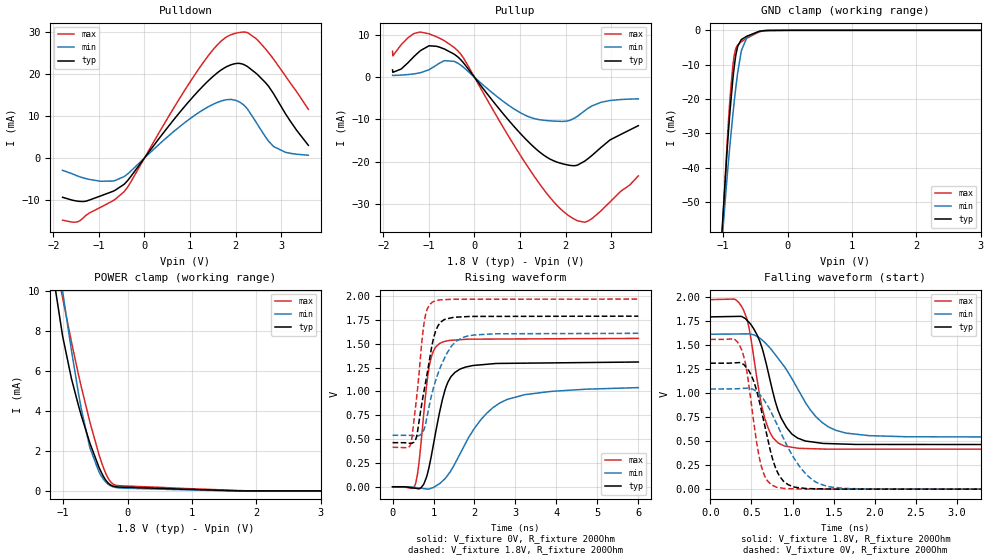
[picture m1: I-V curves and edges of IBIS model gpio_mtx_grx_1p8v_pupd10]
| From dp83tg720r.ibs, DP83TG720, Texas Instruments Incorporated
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|   gpio_mtx_grx_1p8v_pupd10
[Model]   gpio_mtx_grx_1p8v_pupd10
Model_type   I/O
Polarity   Non-Inverting
Enable   Active-Low
Vinl = 0.54
Vinh = 1.26
Vmeas = 0.9
Vref = 0
Cref = 2pF
Rref = 100000
|   typ   min   max
C_comp   1.46pF   1.44pF   1.48pF
[Voltage Range]   1.8   1.62   1.98
[Temperature Range]   27   150   -40
[Pullup Reference]   1.8   1.62   1.98
[Pulldown Reference]   0   0   0
[Power Clamp Reference]   1.8   1.62   1.98
[GND Clamp Reference]   0   0   0
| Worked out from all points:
|   slope of the pulldown table from 0 to 0.27 V, typ, clamps not added: 68.8 ohm
|   slope of the pullup table from 0 to 0.27 V, typ, clamps not added: 71.1 ohm
|   GND clamp passes 1 mA (typ) near -0.54 V on its own axis
|   POWER clamp passes 1 mA (typ) near -0.42 V on its own axis
|   falling waveform, V_fixture 1.8V, R_fixture 200Ohm: 20-80 % time 262ps typ, 492ps min, 192ps max; typ from 1.79 V to 0.463 V
|   rising waveform, V_fixture 0V, R_fixture 200Ohm: 20-80 % time 387ps typ, 980ps min, 228ps max; typ from 0 V to 1.31 V
|   rising waveform, V_fixture 1.8V, R_fixture 200Ohm: 20-80 % time 321ps typ, 472ps min, 220ps max; typ from 0.463 V to 1.79 V
|   falling waveform, V_fixture 0V, R_fixture 200Ohm: 20-80 % time 222ps typ, 390ps min, 160ps max; typ from 1.31 V to 0 V
[Pulldown]
|   Voltage   I(typ)   I(min)   I(max)
-1.8V     -9.373mA   -2.955mA   -14.83mA
-1.503V   -10.24mA   -4.167mA   -15.29mA
-1.287V   -10.3mA    -4.916mA   -13.7mA
-698.4mV  -7.972mA   -5.494mA   -10.23mA
-444.6mV  -6.254mA   -4.425mA   -8.011mA
1.143V    15.5mA     10.46mA    20.44mA
1.597V    20.26mA    13.22mA    26.92mA
1.894V    22.18mA    13.95mA    29.34mA
2.174V    22.29mA    12.67mA    30mA
2.45V     20.2mA     8.58mA     28.46mA
2.839V    15.27mA    2.714mA    23.52mA
3.6V      3.022mA    656uA      11.6mA
[GND Clamp]
|   Voltage   I(typ)   I(min)   I(max)
-1.8V     -346.2mA   -302.9mA   -380.4mA
-1.012V   -56.7mA    -60.05mA   -58.37mA
-941.4mV  -35.77mA   -43.43mA   -33.93mA
-898.2mV  -24.65mA   -34.19mA   -21.03mA
-849.6mV  -14.29mA   -24.7mA    -10.27mA
-833.4mV  -11.45mA   -21.77mA   -7.914mA
-801mV    -6.989mA   -16.32mA   -5.181mA
-774mV    -4.661mA   -12.31mA   -4.247mA
-720mV    -2.755mA   -6.237mA   -3.369mA
-628.2mV  -1.684mA   -1.968mA   -2.249mA
-293.4mV  -41.03uA   -39.78uA   -54.54uA
3.6V      0A         0A         0A
[Pullup]
|   Voltage   I(typ)   I(min)   I(max)
-1.8V     1.744mA    480.7uA    6.165mA
-1.795V   1.177mA    422.4uA    5.078mA
-1.611V   1.951mA    521.8uA    7.703mA
-1.206V   6.14mA     1.032mA    10.69mA
-828mV    7.327mA    2.927mA    9.562mA
-444.6mV  5.46mA     3.759mA    7.052mA
-223.2mV  3.171mA    2.189mA    4.237mA
1.138V    -14.78mA   -9.105mA   -20.64mA
1.672V    -19.44mA   -10.32mA   -28.64mA
2.25V     -20.85mA   -9.32mA    -33.92mA
2.59V     -18.43mA   -6.745mA   -33.39mA
3.6V      -11.46mA   -5.119mA   -23.35mA
[POWER Clamp]
|   Voltage   I(typ)   I(min)   I(max)
-1.8V     53.03mA    32.09mA    32.8mA
-1.13V    10.31mA    12.75mA    11.79mA
-1.006V   7.723mA    9.944mA    9.63mA
-871.2mV  5.628mA    7.042mA    7.462mA
-720mV    3.797mA    4.133mA    5.24mA
-585mV    2.398mA    2.165mA    3.454mA
-444.6mV  1.193mA    960.8uA    1.835mA
-347.4mV  586.3uA    482.8uA    949uA
-271.8mV  317uA      272.9uA    491.2uA
-142.2mV  198.3uA    155.7uA    266.6uA
1.067V    69.49uA    43.45uA    98.19uA
3.6V      0A         0A         0A
[Ramp]
R_load = 200
|   typ   min   max
dV/dt_r   0.785476/3.86403e-10   0.624337/9.79154e-10   0.934047/2.27086e-10
dV/dt_f   0.796658/2.61052e-10   0.642069/4.88383e-10   0.93308/1.91646e-10
[Falling Waveform]
V_fixture = 1.8V
V_fixture_min = 1.62V
V_fixture_max = 1.98V
R_fixture = 200Ohm
C_fixture = 0F
|   Time   V(typ)   V(min)   V(max)
0s        1.791V     1.61V      1.97V
290.4ps   1.795V     1.613V     1.976V
397.8ps   1.787V     1.613V     1.872V
471.5ps   1.733V     1.614V     1.673V
663.8ps   1.358V     1.524V     733.2mV
788.5ps   915.4mV    1.399V     510.8mV
901.7ps   678.6mV    1.273V     448.6mV
1.28ns    486.2mV    757.7mV    419.7mV
1.65ns    468.1mV    582.8mV    416.3mV
6ns       462.8mV    540.3mV    414.9mV
[Rising Waveform]
V_fixture = 0V
V_fixture_min = 0V
V_fixture_max = 0V
R_fixture = 200Ohm
C_fixture = 0F
|   Time   V(typ)   V(min)   V(max)
0s        265.6uV    155.4uV    420.8uV
556.8ps   -15.77mV   -7.668mV   27.88mV
645.8ps   -21.29mV   -12.58mV   254.4mV
888.2ps   200.7mV    -23.76mV   1.247V
1.148ns   783.5mV    33.2mV     1.504V
1.307ns   1.051V     99.22mV    1.528V
1.518ns   1.199V     239.9mV    1.54V
2.133ns   1.279V     691.7mV    1.55V
2.791ns   1.295V     915.3mV    1.551V
6ns       1.309V     1.041V     1.557V
[Rising Waveform]
V_fixture = 1.8V
V_fixture_min = 1.62V
V_fixture_max = 1.98V
R_fixture = 200Ohm
C_fixture = 0F
|   Time   V(typ)   V(min)   V(max)
0s        462.8mV    540.3mV    414.9mV
447.9ps   456.6mV    538.8mV    456.6mV
584.5ps   523.5mV    533.8mV    926.7mV
767.5ps   1.004V     600mV      1.715V
850.8ps   1.204V     755.5mV    1.869V
975.4ps   1.511V     1V         1.938V
1.11ns    1.691V     1.189V     1.958V
1.427ns   1.772V     1.47V      1.967V
1.837ns   1.786V     1.582V     1.968V
6ns       1.791V     1.61V      1.97V
[Falling Waveform]
|Gnd
V_fixture = 0V
V_fixture_min = 0V
V_fixture_max = 0V
R_fixture = 200Ohm
C_fixture = 0F
|   Time   V(typ)   V(min)   V(max)
0s        1.31V      1.041V     1.557V
280.9ps   1.312V     1.042V     1.563V
373.6ps   1.312V     1.046V     1.464V
426ps     1.277V     1.049V     1.311V
495.4ps   1.188V     1.044V     910mV
617.6ps   831.6mV    967.2mV    247.4mV
803.4ps   199.4mV    686.5mV    20.74mV
1.105ns   12.93mV    214.1mV    1.587mV
1.475ns   1.345mV    21.17mV    1.305mV
6ns       265.7uV    155.4uV    421.2uV
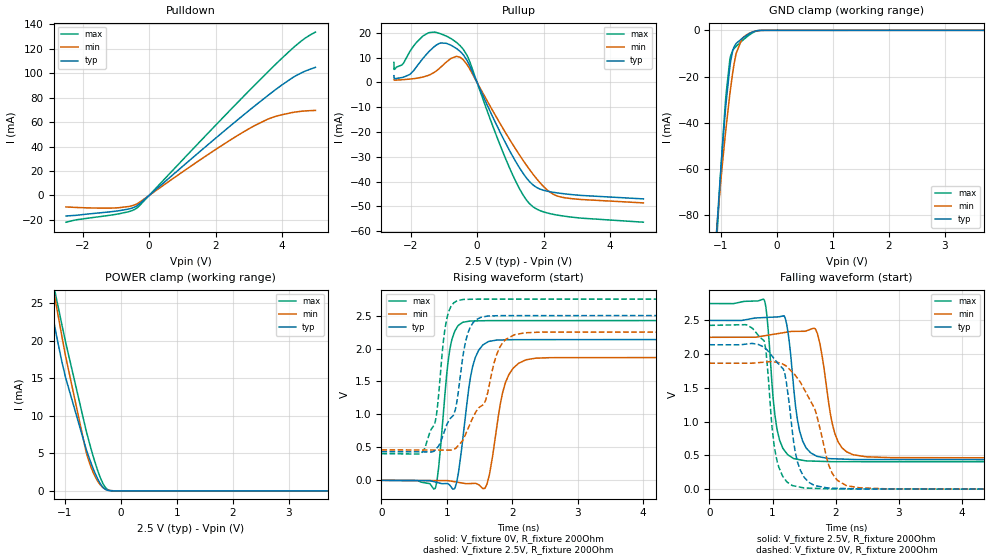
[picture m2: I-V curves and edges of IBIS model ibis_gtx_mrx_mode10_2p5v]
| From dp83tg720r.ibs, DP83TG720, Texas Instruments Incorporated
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| ibis_gtx_mrx_mode10_2p5v
[Model]   ibis_gtx_mrx_mode10_2p5v
Model_type   I/O
Polarity   Non-Inverting
Enable   Active-Low
Vinl = 0.75
Vinh = 1.75
Vmeas = 1.25
Vref = 1.25
Cref = 2pF
Rref = 100000
|   typ   min   max
C_comp   2.91pF   2.87pF   2.94pF
[Voltage Range]   2.5   2.25   2.75
[Temperature Range]   27   150   -40
[Pullup Reference]   2.5   2.25   2.75
[Pulldown Reference]   0   0   0
[Power Clamp Reference]   2.5   2.25   2.75
[GND Clamp Reference]   0   0   0
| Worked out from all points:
|   slope of the pulldown table from 0 to 0.375 V, typ, clamps not added: 42.1 ohm
|   slope of the pullup table from 0 to 0.375 V, typ, clamps not added: 33.6 ohm
|   GND clamp passes 1 mA (typ) near -0.45 V on its own axis
|   POWER clamp passes 1 mA (typ) near -0.37 V on its own axis
|   falling waveform, V_fixture 2.5V, R_fixture 200Ohm: 20-80 % time 157ps typ, 190ps min, 136ps max; typ from 2.5 V to 0.435 V
|   rising waveform, V_fixture 0V, R_fixture 200Ohm: 20-80 % time 171ps typ, 199ps min, 137ps max; typ from 0 V to 2.14 V
|   rising waveform, V_fixture 2.5V, R_fixture 200Ohm: 20-80 % time 283ps typ, 417ps min, 150ps max; typ from 0.435 V to 2.5 V
|   falling waveform, V_fixture 0V, R_fixture 200Ohm: 20-80 % time 194ps typ, 391ps min, 149ps max; typ from 2.14 V to 0 V
[Pulldown]
|   Voltage   I(typ)   I(min)   I(max)
-2.5V     -16.83mA   -9.441mA   -21.92mA
-2.185V   -16.25mA   -9.858mA   -19.94mA
-1.083V   -13.14mA   -10.32mA   -15.85mA
-617.5mV  -11.15mA   -9.099mA   -13.35mA
-362.5mV  -8.408mA   -6.814mA   -10.19mA
1.798V    42.21mA    33.95mA    51.74mA
2.533V    59mA       46.91mA    72.51mA
3.147V    72.69mA    56.82mA    89.62mA
3.74V     85.35mA    64.15mA    105.7mA
4.28V     95.82mA    67.74mA    119.6mA
4.692V    101.8mA    69.17mA    128.8mA
5V        104.8mA    69.59mA    133.7mA
[GND Clamp]
|   Voltage   I(typ)   I(min)   I(max)
-2.5V     -672.4mA   -578.6mA   -749.1mA
-1.097V   -97.01mA   -94.22mA   -103.2mA
-1.03V    -72.28mA   -74.57mA   -74.7mA
-962.5mV  -49.34mA   -56.59mA   -48.07mA
-917.5mV  -35.71mA   -45.65mA   -32.42mA
-835mV    -16.02mA   -27.78mA   -12.86mA
-782.5mV  -8.753mA   -18.2mA    -8.647mA
-722.5mV  -5.688mA   -10.01mA   -6.949mA
-617.5mV  -3.554mA   -3.702mA   -4.596mA
-467.5mV  -1.199mA   -1.052mA   -1.675mA
-272.5mV  -16.77uA   -38.63uA   -18.24uA
5V        0A         0A         0A
[Pullup]
|   Voltage   I(typ)   I(min)   I(max)
-2.5V     2.729mA    1.091mA    8.084mA
-2.493V   1.51mA     925.7uA    5.246mA
-2.268V   1.963mA    1.093mA    7.013mA
-2.02V    3.254mA    1.361mA    12.53mA
-1.472V   12.09mA    2.813mA    19.97mA
-1.135V   15.76mA    5.648mA    19.84mA
-790mV    15.09mA    9.669mA    17.78mA
-287.5mV  8.575mA    6.935mA    10.56mA
852.5mV   -24.33mA   -20.2mA    -30.6mA
1.587V    -40.18mA   -35.34mA   -49.09mA
2.428V    -44.63mA   -45.92mA   -53.59mA
5V        -47.02mA   -48.64mA   -56.43mA
[POWER Clamp]
|   Voltage   I(typ)   I(min)   I(max)
-2.5V     144.5mA    109.4mA    191.7mA
-1.42V    32.38mA    36.09mA    36.29mA
-1.248V   24.72mA    28.69mA    29.23mA
-1.15V    20.76mA    24.63mA    25.64mA
-985mV    15.08mA    17.93mA    19.8mA
-617.5mV  5.56mA     5.156mA    8.015mA
-550mV    4.113mA    3.562mA    6.126mA
-460mV    2.396mA    1.954mA    3.822mA
-355mV    860uA      725.3uA    1.597mA
-257.5mV  148.6uA    170.2uA    327.9uA
-92.5mV   988.6nA    4.315uA    1.238uA
5V        0A         0A         0A
[Ramp]
R_load = 200
|   typ   min   max
dV/dt_r   1.28225/1.70637e-10   1.11858/1.99144e-10   1.45475/1.35625e-10
dV/dt_f   1.23902/1.55855e-10   1.07266/1.89547e-10   1.40735/1.36094e-10
[Falling Waveform]
V_fixture = 2.5V
V_fixture_min = 2.25V
V_fixture_max = 2.75V
R_fixture = 200Ohm
C_fixture = 0F
|   Time   V(typ)   V(min)   V(max)
0s        2.5V       2.25V      2.75V
868ps     2.543V     2.272V     2.805V
1.072ns   2.552V     2.303V     883.2mV
1.206ns   2.516V     2.324V     551.9mV
1.331ns   1.534V     2.338V     454.3mV
1.476ns   714.1mV    2.339V     428mV
1.681ns   497.3mV    2.367V     414.6mV
1.98ns    449.8mV    842.3mV    407.3mV
2.267ns   440.4mV    512.7mV    407.1mV
6ns       435mV      462.3mV    404.5mV
[Rising Waveform]
V_fixture = 0V
V_fixture_min = 0V
V_fixture_max = 0V
R_fixture = 200Ohm
C_fixture = 0F
|   Time   V(typ)   V(min)   V(max)
0s        1.569uV    20.51uV    733.6nV
820.6ps   -24.9mV    -2.975mV   -123.4mV
1.044ns   -71mV      -8.529mV   1.974V
1.149ns   -35.57mV   -26.32mV   2.31V
1.239ns   587.4mV    -41.45mV   2.395V
1.489ns   1.977V     -67.63mV   2.42V
1.614ns   2.093V     -55.32mV   2.422V
1.898ns   2.131V     1.487V     2.423V
2.199ns   2.134V     1.824V     2.423V
6ns       2.137V     1.864V     2.425V
[Rising Waveform]
V_fixture = 2.5V
V_fixture_min = 2.25V
V_fixture_max = 2.75V
R_fixture = 200Ohm
C_fixture = 0F
|   Time   V(typ)   V(min)   V(max)
0s        435mV      462.3mV    404.5mV
661.8ps   431.7mV    460.1mV    483.6mV
835.1ps   475.7mV    459.5mV    954.5mV
998.4ps   842.9mV    458.9mV    2.45V
1.16ns    1.237V     512.6mV    2.727V
1.287ns   2.108V     700.3mV    2.745V
1.403ns   2.393V     959.8mV    2.748V
1.808ns   2.499V     2.015V     2.749V
2.035ns   2.499V     2.209V     2.749V
6ns       2.5V       2.25V      2.75V
[Falling Waveform]
|Gnd
V_fixture = 0V
V_fixture_min = 0V
V_fixture_max = 0V
R_fixture = 200Ohm
C_fixture = 0F
|   Time   V(typ)   V(min)   V(max)
0s        2.14V      1.866V     2.427V
861.8ps   2.1V       1.881V     2.203V
1.053ns   1.9V       1.881V     495.4mV
1.192ns   1.72V      1.837V     151.6mV
1.311ns   868.5mV    1.734V     54.28mV
1.398ns   393.2mV    1.639V     36.98mV
1.571ns   102.8mV    1.358V     15.15mV
1.935ns   16.12mV    253.8mV    3.348mV
2.163ns   8.783mV    55.26mV    2.931mV
6ns       1.684uV    20.54uV    725.1nV
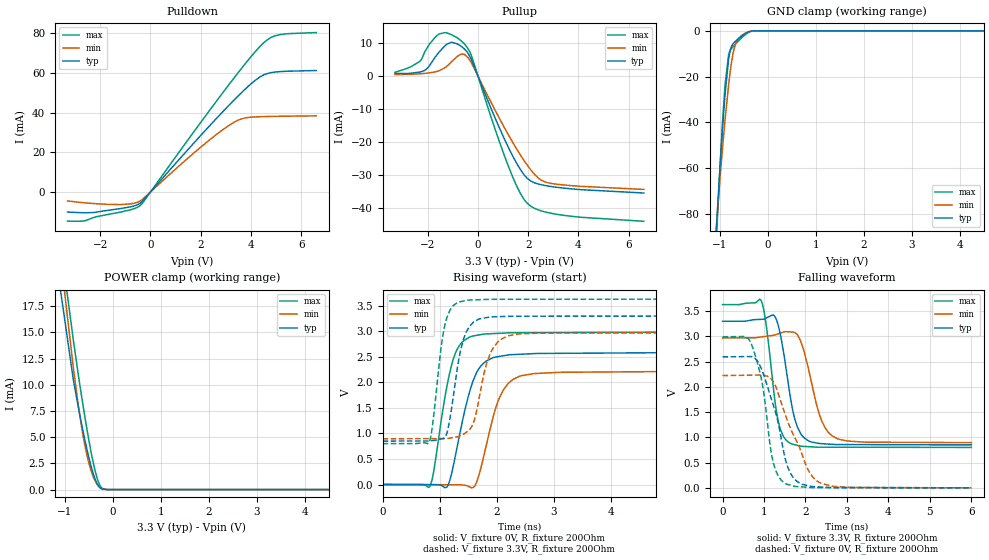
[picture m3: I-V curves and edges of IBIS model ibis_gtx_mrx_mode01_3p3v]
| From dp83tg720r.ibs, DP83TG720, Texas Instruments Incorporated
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| ibis_gtx_mrx_mode10_3p3v
[Model]   ibis_gtx_mrx_mode01_3p3v
Model_type   I/O
Polarity   Non-Inverting
Enable   Active-Low
Vinl = 0.99
Vinh = 2.31
Vmeas = 1.65
Vref = 1.65
Cref = 2pF
Rref = 100000
|   typ   min   max
C_comp   2.88pF   2.85pF   2.91pF
[Voltage Range]   3.3   2.97   3.63
[Temperature Range]   27   150   -40
[Pullup Reference]   3.3   2.97   3.63
[Pulldown Reference]   0   0   0
[Power Clamp Reference]   3.3   2.97   3.63
[GND Clamp Reference]   0   0   0
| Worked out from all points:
|   slope of the pulldown table from 0 to 0.495 V, typ, clamps not added: 69.2 ohm
|   slope of the pullup table from 0 to 0.495 V, typ, clamps not added: 53.2 ohm
|   GND clamp passes 1 mA (typ) near -0.45 V on its own axis
|   POWER clamp passes 1 mA (typ) near -0.37 V on its own axis
|   falling waveform, V_fixture 3.3V, R_fixture 200Ohm: 20-80 % time 306ps typ, 389ps min, 253ps max; typ from 3.3 V to 0.85 V
|   rising waveform, V_fixture 0V, R_fixture 200Ohm: 20-80 % time 333ps typ, 333ps min, 278ps max; typ from 0 V to 2.59 V
|   rising waveform, V_fixture 3.3V, R_fixture 200Ohm: 20-80 % time 221ps typ, 262ps min, 183ps max; typ from 0.85 V to 3.3 V
|   falling waveform, V_fixture 0V, R_fixture 200Ohm: 20-80 % time 474ps typ, 637ps min, 330ps max; typ from 2.59 V to 0 V
[Pulldown]
|   Voltage   I(typ)   I(min)   I(max)
-3.3V     -10.08mA   -4.49mA    -14.66mA
-2.666V   -10.42mA   -5.368mA   -14.59mA
-2.28V    -10.33mA   -5.764mA   -12.91mA
-1.211V   -8.365mA   -6.324mA   -10.16mA
-429mV    -5.796mA   -4.673mA   -6.987mA
1.818V    25.94mA    20.63mA    31.91mA
2.986V    41.87mA    32.34mA    51.81mA
3.62V     49.98mA    36.81mA    62.2mA
4.392V    58.22mA    37.95mA    73.74mA
4.769V    60.04mA    38.06mA    77.63mA
4.966V    60.42mA    38.11mA    78.69mA
6.6V      61.18mA    38.36mA    80.29mA
[GND Clamp]
|   Voltage   I(typ)   I(min)   I(max)
-3.3V     -1.011A    -865.8mA   -1.126A
-1.082V   -91.37mA   -89.71mA   -96.69mA
-1.053V   -80.45mA   -81.02mA   -84.12mA
-963.6mV  -49.69mA   -56.87mA   -48.48mA
-894.3mV  -29.4mA    -40.34mA   -25.48mA
-815.1mV  -12.66mA   -23.94mA   -10.6mA
-765.6mV  -7.479mA   -15.54mA   -8.067mA
-726mV    -5.787mA   -10.39mA   -7.032mA
-676.5mV  -4.645mA   -6.247mA   -5.893mA
-567.6mV  -2.701mA   -2.49mA    -3.55mA
-419.1mV  -641.7uA   -598uA     -944.7uA
6.6V      0A         0A         0A
[Pullup]
|   Voltage   I(typ)   I(min)   I(max)
-3.3V     793.6uA    461.8uA    1.11mA
-2.33V    1.194mA    667.6uA    4.324mA
-2.132V   1.671mA    787.5uA    7.026mA
-1.538V   7.318mA    1.632mA    12.73mA
-1.053V   10.25mA    4.299mA    12.52mA
-815.1mV  9.709mA    6.001mA    11.52mA
-537.9mV  8.156mA    6.499mA    9.707mA
-280.5mV  5.302mA    4.258mA    6.565mA
1.125V    -20.21mA   -16.6mA    -25.56mA
1.957V    -30.89mA   -26.91mA   -38.43mA
2.788V    -33.27mA   -32.3mA    -41.31mA
6.6V      -35.38mA   -34.29mA   -43.94mA
[POWER Clamp]
|   Voltage   I(typ)   I(min)   I(max)
-3.3V     317.9mA    237mA      400.5mA
-1.181V   21.99mA    25.93mA    26.78mA
-815.1mV  10.35mA    11.45mA    14.1mA
-656.7mV  6.45mA     6.234mA    9.162mA
-587.4mV  4.9mA      4.403mA    7.158mA
-528mV    3.668mA    3.117mA    5.537mA
-458.7mV  2.373mA    1.935mA    3.791mA
-369.6mV  1.032mA    856.8uA    1.866mA
-310.2mV  435.4uA    402.4uA    888uA
-231mV    77.39uA    103.3uA    169.6uA
-62.7mV   288.6nA    1.815uA    282.8nA
6.6V      0A         0A         0A
[Ramp]
R_load = 200
|   typ   min   max
dV/dt_r   1.55273/3.31035e-10   1.3319/3.30138e-10   1.79224/2.77973e-10
dV/dt_f   1.46973/3.03358e-10   1.24475/3.85363e-10   1.69754/2.53071e-10
[Falling Waveform]
V_fixture = 3.3V
V_fixture_min = 2.97V
V_fixture_max = 3.63V
R_fixture = 200Ohm
C_fixture = 0F
|   Time   V(typ)   V(min)   V(max)
0s        3.3V       2.97V      3.63V
934.3ps   3.338V     2.989V     3.709V
1.053ns   3.363V     3.003V     3.228V
1.295ns   3.344V     3.038V     1.539V
1.458ns   2.753V     3.083V     1.036V
1.626ns   1.85V      3.09V      885.9mV
1.92ns    1.033V     2.821V     823.6mV
2.324ns   880.7mV    1.485V     805.4mV
2.64ns    862.5mV    1.034V     805mV
6ns       850.3mV    895.2mV    800.7mV
[Rising Waveform]
V_fixture = 0V
V_fixture_min = 0V
V_fixture_max = 0V
R_fixture = 200Ohm
C_fixture = 0F
|   Time   V(typ)   V(min)   V(max)
0s        2.566uV    32.31uV    1.213uV
825.4ps   -2.166mV   -3.183mV   -39.96mV
893.8ps   -2.345mV   -3.449mV   249.4mV
1.151ns   1.238mV    -4.451mV   2.064V
1.303ns   723mV      -5.041mV   2.642V
1.518ns   1.797V     -44.61mV   2.884V
1.653ns   2.208V     68.62mV    2.922V
2.041ns   2.509V     1.69V      2.961V
2.394ns   2.55V      2.119V     2.972V
6ns       2.588V     2.22V      2.987V
[Rising Waveform]
V_fixture = 3.3V
V_fixture_min = 2.97V
V_fixture_max = 3.63V
R_fixture = 200Ohm
C_fixture = 0F
|   Time   V(typ)   V(min)   V(max)
0s        850.3mV    895.2mV    800.7mV
814.3ps   853.4mV    898.9mV    821.4mV
1.077ns   909.4mV    900.1mV    3.056V
1.171ns   1.242V     907.8mV    3.393V
1.324ns   2.386V     938.8mV    3.57V
1.42ns    2.857V     987.5mV    3.594V
1.596ns   3.186V     1.232V     3.615V
1.877ns   3.279V     2.546V     3.626V
2.204ns   3.293V     2.913V     3.627V
6ns       3.3V       2.97V      3.63V
[Falling Waveform]
|Gnd
V_fixture = 0V
V_fixture_min = 0V
V_fixture_max = 0V
R_fixture = 200Ohm
C_fixture = 0F
|   Time   V(typ)   V(min)   V(max)
0s        2.593V     2.224V     2.991V
532.5ps   2.6V       2.23V      2.998V
694.4ps   2.6V       2.232V     2.852V
959.6ps   2.311V     2.235V     2.066V
1.219ns   1.654V     2.108V     518.2mV
1.496ns   635.4mV    1.491V     95.94mV
1.774ns   141.8mV    945mV      26.55mV
2.119ns   32.99mV    277mV      8.053mV
2.389ns   14.95mV    85.06mV    5.407mV
6ns       2.644uV    32.39uV    1.331uV
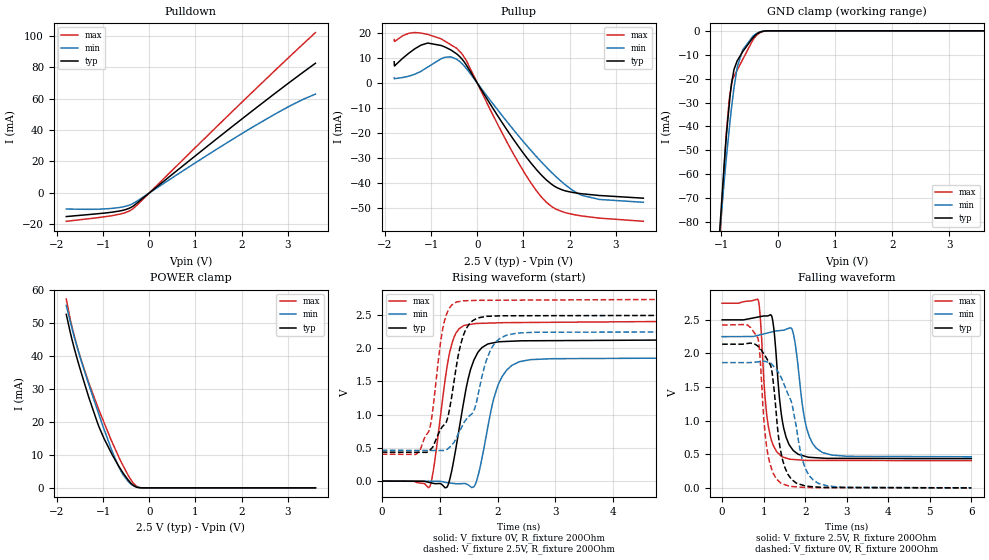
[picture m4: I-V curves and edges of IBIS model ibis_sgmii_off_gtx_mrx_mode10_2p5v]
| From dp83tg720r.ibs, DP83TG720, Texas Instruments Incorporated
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| ibis_sgmii_off_gtx_mrx_mode10_2p5v
[Model]   ibis_sgmii_off_gtx_mrx_mode10_2p5v
Model_type   I/O
Polarity   Non-Inverting
Enable   Active-Low
Vinl = 0.75
Vinh = 1.75
Vmeas = 1.25
Vref = 1.25
Cref = 2pF
Rref = 100000
|   typ   min   max
C_comp   3.97pF   3.9pF   4.02pF
[Voltage Range]   2.5   2.25   2.75
[Temperature Range]   27   150   -40
[Pullup Reference]   2.5   2.25   2.75
[Pulldown Reference]   0   0   0
[Power Clamp Reference]   2.5   2.25   2.75
[GND Clamp Reference]   0   0   0
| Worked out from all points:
|   slope of the pulldown table from 0 to 0.375 V, typ, clamps not added: 42.1 ohm
|   slope of the pullup table from 0 to 0.375 V, typ, clamps not added: 33.6 ohm
|   GND clamp passes 1 mA (typ) near -0.35 V on its own axis
|   POWER clamp passes 1 mA (typ) near -0.37 V on its own axis
|   falling waveform, V_fixture 2.5V, R_fixture 200Ohm: 20-80 % time 213ps typ, 256ps min, 181ps max; typ from 2.5 V to 0.435 V
|   rising waveform, V_fixture 0V, R_fixture 200Ohm: 20-80 % time 276ps typ, 292ps min, 228ps max; typ from 0 V to 2.12 V
|   rising waveform, V_fixture 2.5V, R_fixture 200Ohm: 20-80 % time 293ps typ, 453ps min, 202ps max; typ from 0.435 V to 2.49 V
|   falling waveform, V_fixture 0V, R_fixture 200Ohm: 20-80 % time 247ps typ, 434ps min, 193ps max; typ from 2.14 V to 0 V
[Pulldown]
|   Voltage   I(typ)   I(min)   I(max)
-1.8V     -15.04mA   -10.25mA   -18.05mA
-1.319V   -13.79mA   -10.45mA   -16.44mA
-817.2mV  -12.3mA    -9.857mA   -14.51mA
-514.8mV  -10.6mA    -8.511mA   -12.48mA
-358.2mV  -8.505mA   -6.777mA   -10.12mA
1.165V    27.5mA     22.27mA    33.64mA
2.191V    51.23mA    40.99mA    62.89mA
3.06V     70.77mA    55.5mA     87.2mA
3.6V      82.43mA    62.79mA    101.9mA
[GND Clamp]
|   Voltage   I(typ)   I(min)   I(max)
-1.8V     -413mA     -361.3mA   -461.4mA
-1.022V   -83.07mA   -84.73mA   -87.93mA
-941.4mV  -54.43mA   -61.85mA   -55.74mA
-909mV    -44.33mA   -53.48mA   -43.2mA
-855mV    -30.36mA   -40.67mA   -28.24mA
-801mV    -19.85mA   -29.07mA   -20.25mA
-774mV    -16.2mA    -23.83mA   -19.01mA
-714.6mV  -12.41mA   -15.06mA   -16.28mA
-622.8mV  -8.77mA    -8.034mA   -12.06mA
-385.2mV  -1.536mA   -1.214mA   -2.105mA
-185.4mV  -22.8uA    -32.29uA   -35.92uA
3.6V      0A         0A         0A
[Pullup]
|   Voltage   I(typ)   I(min)   I(max)
-1.8V     8.497mA    2.004mA    17.38mA
-1.795V   6.823mA    1.742mA    16.64mA
-1.481V   11.97mA    2.768mA    19.91mA
-1.071V   16mA       6.424mA    19.46mA
-698.4mV  14.41mA    10.33mA    16.74mA
-574.2mV  13.27mA    10.49mA    15.34mA
-336.6mV  9.715mA    7.883mA    11.8mA
910.8mV   -25.84mA   -21.5mA    -32.46mA
1.31V     -35.21mA   -29.99mA   -43.78mA
1.618V    -40.6mA    -35.9mA    -49.48mA
2.261V    -44.29mA   -44.91mA   -53.17mA
3.6V      -46.07mA   -47.71mA   -55.32mA
[POWER Clamp]
|   Voltage   I(typ)   I(min)   I(max)
-1.8V     52.72mA    55.43mA    57.36mA
-1.681V   45.36mA    48.74mA    49.19mA
-1.546V   38.34mA    41.85mA    42.08mA
-1.319V   27.84mA    31.74mA    32.21mA
-1.082V   18.24mA    21.83mA    23.29mA
-979.2mV  14.91mA    17.7mA     19.75mA
-806.4mV  10.12mA    11.14mA    13.88mA
-612mV    5.438mA    5.014mA    7.891mA
-444.6mV  2.133mA    1.733mA    3.461mA
-293.4mV  326uA      317uA      674.2uA
-109.8mV  6.029uA    13.64uA    2.639uA
3.6V      0A         0A         0A
[Ramp]
R_load = 200
|   typ   min   max
dV/dt_r   1.27515/2.74847e-10   1.11168/2.90571e-10   1.44393/2.27125e-10
dV/dt_f   1.23858/2.10584e-10   1.07224/2.5313e-10   1.40527/1.79151e-10
[Falling Waveform]
V_fixture = 2.5V
V_fixture_min = 2.25V
V_fixture_max = 2.75V
R_fixture = 200Ohm
C_fixture = 0F
|   Time   V(typ)   V(min)   V(max)
0s        2.5V       2.25V      2.747V
864.5ps   2.541V     2.27V      2.802V
917.6ps   2.548V     2.278V     2.548V
1.065ns   2.557V     2.3V       1.142V
1.207ns   2.525V     2.321V     671.9mV
1.428ns   1.087V     2.343V     470.2mV
1.695ns   570.9mV    2.341V     423.2mV
2.025ns   465mV      915.5mV    408.8mV
2.404ns   443mV      530.3mV    408.4mV
6ns       435.3mV    462.5mV    404.7mV
[Rising Waveform]
V_fixture = 0V
V_fixture_min = 0V
V_fixture_max = 0V
R_fixture = 200Ohm
C_fixture = 0F
|   Time   V(typ)   V(min)   V(max)
0s        75.12uV    60.61uV    78.55uV
829.6ps   -21.96mV   -1.912mV   -84.81mV
1.139ns   -72.69mV   -25.65mV   1.775V
1.248ns   332.7mV    -36.3mV    2.16V
1.41ns    1.159V     -37.46mV   2.335V
1.598ns   1.829V     -78.7mV    2.365V
1.73ns    2.006V     340.7mV    2.372V
2.012ns   2.094V     1.448V     2.379V
2.368ns   2.107V     1.791V     2.383V
6ns       2.125V     1.853V     2.407V
[Rising Waveform]
V_fixture = 2.5V
V_fixture_min = 2.25V
V_fixture_max = 2.75V
R_fixture = 200Ohm
C_fixture = 0F
|   Time   V(typ)   V(min)   V(max)
0s        435.1mV    462.3mV    404.6mV
664.7ps   432.3mV    460.7mV    471.9mV
845.9ps   477.7mV    460.3mV    860.3mV
1.015ns   773.5mV    459.9mV    2.078V
1.118ns   895.3mV    471.3mV    2.507V
1.275ns   1.648V     625.9mV    2.685V
1.512ns   2.361V     977.6mV    2.713V
1.877ns   2.479V     1.965V     2.718V
2.156ns   2.485V     2.193V     2.72V
6ns       2.492V     2.242V     2.735V
[Falling Waveform]
|Gnd
V_fixture = 0V
V_fixture_min = 0V
V_fixture_max = 0V
R_fixture = 200Ohm
C_fixture = 0F
|   Time   V(typ)   V(min)   V(max)
0s        2.138V     1.863V     2.421V
857.6ps   2.11V      1.874V     2.234V
1.008ns   1.99V      1.883V     986.8mV
1.083ns   1.913V     1.873V     567.5mV
1.207ns   1.701V     1.831V     253.7mV
1.41ns    552.9mV    1.656V     72.46mV
1.675ns   125.2mV    1.262V     20.98mV
1.977ns   33.15mV    334.5mV    6.159mV
2.294ns   11.53mV    75.29mV    4.477mV
6ns       231uV      257.1uV    230uV
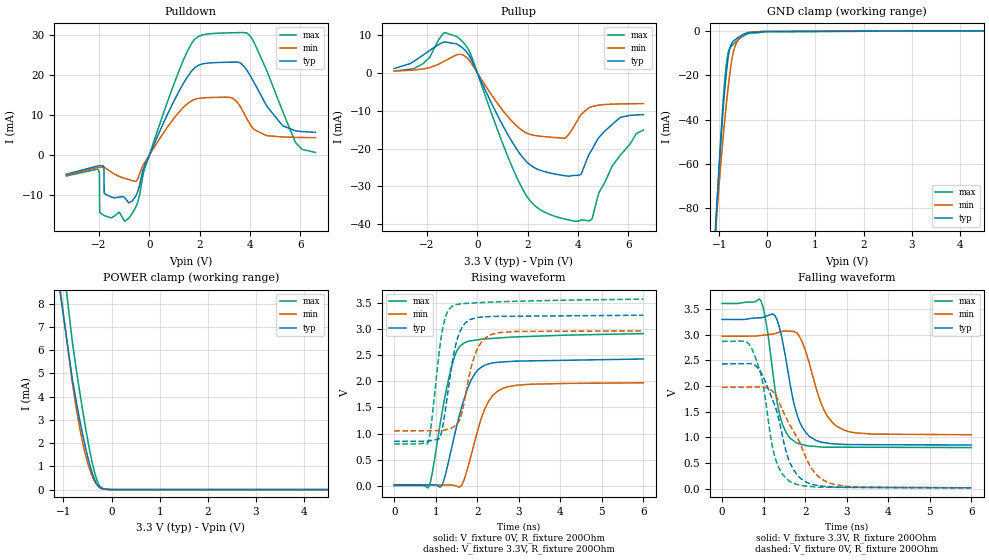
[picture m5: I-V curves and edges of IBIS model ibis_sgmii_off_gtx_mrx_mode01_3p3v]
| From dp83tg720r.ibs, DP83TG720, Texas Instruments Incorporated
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| ibis_sgmii_off_gtx_mrx_mode01_3p3v
[Model]   ibis_sgmii_off_gtx_mrx_mode01_3p3v
Model_type   I/O
Polarity   Non-Inverting
Enable   Active-Low
Vinl = 0.99
Vinh = 2.31
Vmeas = 1.65
Vref = 1.65
Cref = 2pF
Rref = 100000
|   typ   min   max
C_comp   3.97pF   3.94pF   4.02pF
[Voltage Range]   3.3   2.97   3.63
[Temperature Range]   27   150   -40
[Pullup Reference]   3.3   2.97   3.63
[Pulldown Reference]   0   0   -0
[Power Clamp Reference]   3.3   2.97   3.63
[GND Clamp Reference]   0   0   0
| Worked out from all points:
|   slope of the pulldown table from 0 to 0.495 V, typ, clamps not added: 69.8 ohm
|   slope of the pullup table from 0 to 0.495 V, typ, clamps not added: 70 ohm
|   GND clamp passes 1 mA (typ) near -0.41 V on its own axis
|   POWER clamp passes 1 mA (typ) near -0.44 V on its own axis
|   falling waveform, V_fixture 3.3V, R_fixture 200Ohm: 20-80 % time 379ps typ, 474ps min, 316ps max; typ from 3.3 V to 0.851 V
|   rising waveform, V_fixture 0V, R_fixture 200Ohm: 20-80 % time 491ps typ, 456ps min, 412ps max; typ from 0.017 V to 2.43 V
|   rising waveform, V_fixture 3.3V, R_fixture 200Ohm: 20-80 % time 301ps typ, 340ps min, 252ps max; typ from 0.85 V to 3.27 V
|   falling waveform, V_fixture 0V, R_fixture 200Ohm: 20-80 % time 528ps typ, 717ps min, 372ps max; typ from 2.43 V to 0.017 V
[Pulldown]
|   Voltage   I(typ)   I(min)   I(max)
-3.3V     -4.719mA   -4.999mA   -5.168mA
-2.053V   -2.68mA    -3.057mA   -3.452mA
-1.983V   -2.621mA   -3.002mA   -4.385mA
-1.973V   -2.615mA   -2.995mA   -14.23mA
-1.805V   -2.89mA    -3.001mA   -14.96mA
-1.795V   -9.503mA   -3.012mA   -15mA
-815.1mV  -11.85mA   -6.047mA   -15.67mA
1.403V    18.4mA     12.2mA     24.38mA
2.373V    22.96mA    14.35mA    30.22mA
4.036V    19.52mA    7.386mA    29.4mA
5.808V    6.077mA    4.441mA    3.172mA
6.6V      5.691mA    4.366mA    685.5uA
[GND Clamp]
|   Voltage   I(typ)   I(min)   I(max)
-3.3V     -1.009A    -875.1mA   -1.118A
-1.142V   -111.9mA   -110.4mA   -118.5mA
-1.063V   -82.54mA   -86.24mA   -85.2mA
-933.9mV  -39.49mA   -51.44mA   -36.28mA
-894.3mV  -28.55mA   -42.1mA    -24.32mA
-854.7mV  -19.22mA   -33.4mA    -15.15mA
-785.4mV  -8.345mA   -20.06mA   -8.01mA
-706.2mV  -4.673mA   -9.544mA   -6.024mA
-617.1mV  -3.175mA   -4.396mA   -4.286mA
-468.6mV  -1.371mA   -1.246mA   -1.938mA
-52.8mV   -339.3uA   -253.8uA   -459.7uA
6.6V      0A         0A         0A
[Pullup]
|   Voltage   I(typ)   I(min)   I(max)
-3.3V     1.091mA    447uA      427.8uA
-2.122V   4.778mA    1.017mA    2.478mA
-1.3V     8.14mA     3.102mA    10.59mA
-676.5mV  7.008mA    4.855mA    8.806mA
-260.7mV  3.771mA    2.752mA    4.883mA
1.828V    -22.51mA   -15.43mA   -31.06mA
2.402V    -25.49mA   -16.68mA   -35.7mA
3.501V    -27.2mA    -17.24mA   -38.65mA
4.125V    -26.74mA   -11.07mA   -38.85mA
4.551V    -20.34mA   -8.951mA   -38.6mA
5.353V    -13.71mA   -8.299mA   -24.72mA
6.6V      -11.07mA   -8.164mA   -15.13mA
[POWER Clamp]
|   Voltage   I(typ)   I(min)   I(max)
-3.3V     249.7mA    167.6mA    340.7mA
-1.28V    11.59mA    11.98mA    14.68mA
-815.1mV  4.758mA    4.603mA    6.362mA
-735.9mV  3.82mA     3.542mA    5.219mA
-656.7mV  2.949mA    2.601mA    4.138mA
-518.1mV  1.613mA    1.315mA    2.402mA
-438.9mV  973.3uA    783.3uA    1.534mA
-359.7mV  469.1uA    395.1uA    803.1uA
-300.3mV  215.2uA    201.9uA    390.6uA
-211.2mV  49.29uA    58.12uA    78.78uA
16.5mV    0A         0A         0A
6.6V      0A         0A         0A
[Ramp]
R_load = 200
|   typ   min   max
dV/dt_r   1.4488/4.88231e-10   1.17509/4.5392e-10   1.75094/4.10549e-10
dV/dt_f   1.46812/3.76373e-10   1.1515/4.72336e-10   1.68463/3.15288e-10
[Falling Waveform]
V_fixture = 3.3V
V_fixture_min = 2.97V
V_fixture_max = 3.63V
R_fixture = 200Ohm
C_fixture = 0F
|   Time   V(typ)   V(min)   V(max)
0s        3.298V     2.97V      3.609V
932.8ps   3.33V      2.986V     3.662V
1.059ns   3.361V     2.998V     3.24V
1.326ns   3.28V      3.036V     1.671V
1.539ns   2.506V     3.072V     1.096V
1.76ns    1.567V     3.049V     908.1mV
2.1ns     1.02V      2.442V     832.2mV
2.38ns    909.4mV    1.67V      813.2mV
2.755ns   870.7mV    1.219V     808.8mV
6ns       850.8mV    1.051V     801.2mV
[Rising Waveform]
V_fixture = 0V
V_fixture_min = 0V
V_fixture_max = 0V
R_fixture = 200Ohm
C_fixture = 0F
|   Time   V(typ)   V(min)   V(max)
0s        16.71mV    15.93mV    114.6uV
837.4ps   14.93mV    13.37mV    -13.06mV
1.16ns    27.39mV    12.38mV    1.438V
1.444ns   938.2mV    3.799mV    2.456V
1.601ns   1.438V     -16.76mV   2.689V
1.691ns   1.68V      134.7mV    2.742V
1.942ns   2.151V     855.8mV    2.792V
2.179ns   2.31V      1.466V     2.816V
2.599ns   2.374V     1.862V     2.839V
6ns       2.431V     1.974V     2.918V
[Rising Waveform]
V_fixture = 3.3V
V_fixture_min = 2.97V
V_fixture_max = 3.63V
R_fixture = 200Ohm
C_fixture = 0F
|   Time   V(typ)   V(min)   V(max)
0s        850.4mV    1.051V     800.8mV
819.3ps   853.2mV    1.055V     829.8mV
1.136ns   1.011V     1.056V     2.866V
1.269ns   1.662V     1.077V     3.314V
1.402ns   2.386V     1.114V     3.448V
1.578ns   2.946V     1.264V     3.487V
1.713ns   3.124V     1.721V     3.498V
1.969ns   3.22V      2.565V     3.509V
2.331ns   3.247V     2.899V     3.524V
6ns       3.272V     2.97V      3.58V
[Falling Waveform]
|Gnd
V_fixture = 0V
V_fixture_min = 0V
V_fixture_max = 0V
R_fixture = 200Ohm
C_fixture = 0F
|   Time   V(typ)   V(min)   V(max)
0s        2.431V     1.974V     2.87V
538.1ps   2.436V     1.979V     2.876V
717.2ps   2.433V     1.981V     2.723V
971.6ps   2.21V      1.983V     2.09V
1.17ns    1.824V     1.926V     997.7mV
1.269ns   1.618V     1.844V     620.6mV
1.642ns   490.9mV    1.226V     136.4mV
2.155ns   88.77mV    392mV      40.94mV
2.599ns   37.53mV    107mV      27.32mV
6ns       16.71mV    15.93mV    18.64mV
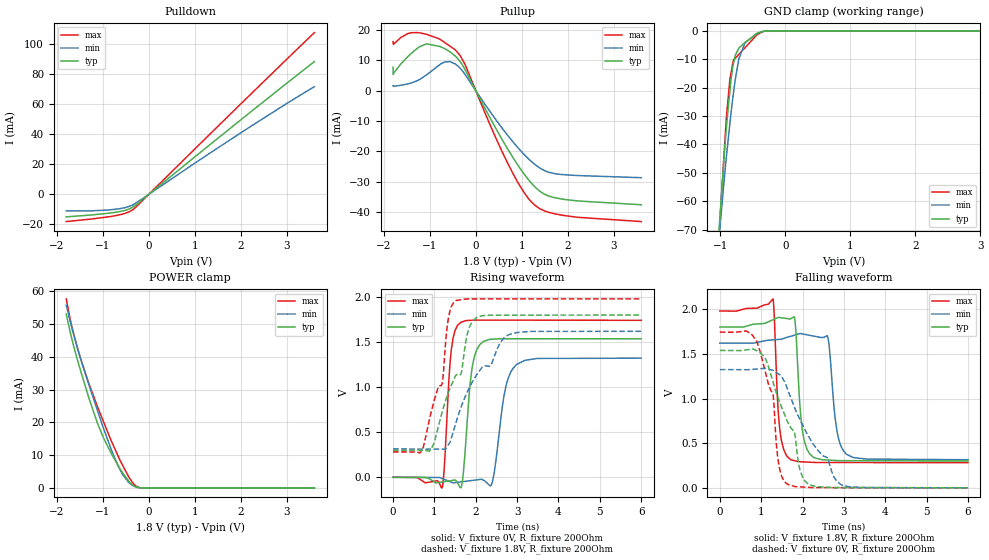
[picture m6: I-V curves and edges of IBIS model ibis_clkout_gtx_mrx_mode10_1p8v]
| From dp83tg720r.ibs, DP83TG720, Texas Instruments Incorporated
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| ibis_clkout_gtx_mrx_mode10_1p8v
[Model]   ibis_clkout_gtx_mrx_mode10_1p8v
Model_type   I/O
Polarity   Non-Inverting
Enable   Active-Low
Vinl = 0.54
Vinh = 1.26
Vmeas = 0.9
Vref = 0.9
Cref = 2pF
Rref = 100000
|   typ   min   max
C_comp   2.97pF   2.96pF   3.01pF
[Voltage Range]   1.8   1.62   1.98
[Temperature Range]   27   150   -40
[Pullup Reference]   1.8   1.62   1.98
[Pulldown Reference]   0   0   0
[Power Clamp Reference]   1.8   1.62   1.98
[GND Clamp Reference]   0   0   0
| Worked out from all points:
|   slope of the pulldown table from 0 to 0.27 V, typ, clamps not added: 40.2 ohm
|   slope of the pullup table from 0 to 0.27 V, typ, clamps not added: 34.5 ohm
|   GND clamp passes 1 mA (typ) near -0.44 V on its own axis
|   POWER clamp passes 1 mA (typ) near -0.37 V on its own axis
|   falling waveform, V_fixture 1.8V, R_fixture 200Ohm: 20-80 % time 144ps typ, 173ps min, 120ps max; typ from 1.8 V to 0.301 V
|   rising waveform, V_fixture 0V, R_fixture 200Ohm: 20-80 % time 171ps typ, 249ps min, 135ps max; typ from 0 V to 1.54 V
|   rising waveform, V_fixture 1.8V, R_fixture 200Ohm: 20-80 % time 641ps typ, 960ps min, 432ps max; typ from 0.301 V to 1.8 V
|   falling waveform, V_fixture 0V, R_fixture 200Ohm: 20-80 % time 634ps typ, 977ps min, 352ps max; typ from 1.54 V to 0 V
[Pulldown]
|   Voltage   I(typ)   I(min)   I(max)
-1.8V     -15.05mA   -11.15mA   -18.18mA
-1.249V   -13.77mA   -11.04mA   -16.47mA
-730.8mV  -12mA      -9.978mA   -14.25mA
-520.2mV  -10.73mA   -8.924mA   -12.73mA
-336.6mV  -8.236mA   -6.801mA   -9.935mA
2.072V    51.2mA     42.22mA    62.18mA
3.6V      88.11mA    71.44mA    107.4mA
[GND Clamp]
|   Voltage   I(typ)   I(min)   I(max)
-1.8V     -382.3mA   -332mA     -425.2mA
-1.017V   -68.67mA   -71.81mA   -70.53mA
-903.6mV  -32.69mA   -43.18mA   -29.12mA
-855mV    -21.28mA   -32.69mA   -17.07mA
-838.8mV  -17.47mA   -29.2mA    -15.06mA
-801mV    -11.68mA   -22.1mA    -10.37mA
-774mV    -8.705mA   -17.42mA   -9.699mA
-714.6mV  -6.046mA   -9.737mA   -8.229mA
-622.8mV  -4.089mA   -4.277mA   -5.956mA
-444.6mV  -1.097mA   -993.2uA   -1.545mA
-261mV    -16.1uA    -40.43uA   -15.49uA
3.6V      0A         0A         0A
[Pullup]
|   Voltage   I(typ)   I(min)   I(max)
-1.8V     7.681mA    1.604mA    16.16mA
-1.795V   5.348mA    1.43mA     15.28mA
-1.476V   11.23mA    2.226mA    18.8mA
-1.071V   15.41mA    5.19mA     18.56mA
-682.2mV  13.87mA    9.394mA    15.91mA
-444.6mV  11.36mA    8.791mA    13.43mA
-239.4mV  7.082mA    5.45mA     8.807mA
343.8mV   -9.894mA   -7.602mA   -12.4mA
797.4mV   -21.76mA   -16.66mA   -26.96mA
1.294V    -31.83mA   -24.41mA   -37.86mA
1.845V    -35.65mA   -27.6mA    -40.95mA
3.6V      -37.6mA    -28.68mA   -43.14mA
[POWER Clamp]
|   Voltage   I(typ)   I(min)   I(max)
-1.8V     53.01mA    55.74mA    57.65mA
-1.681V   45.61mA    49.02mA    49.43mA
-1.546V   38.55mA    42.1mA     42.27mA
-1.319V   27.98mA    31.92mA    32.33mA
-1.114V   19.49mA    23.28mA    24.54mA
-973.8mV  14.8mA     17.58mA    19.66mA
-666mV    6.684mA    6.531mA    9.544mA
-558mV    4.288mA    3.744mA    6.479mA
-444.6mV  2.137mA    1.736mA    3.468mA
-293.4mV  327.2uA    317.2uA    675uA
-109.8mV  6.037uA    13.6uA     2.646uA
3.6V      0A         0A         0A
[Ramp]
R_load = 200
|   typ   min   max
dV/dt_r   0.922137/1.70689e-10   0.793118/2.47286e-10   1.0453/1.34806e-10
dV/dt_f   0.899515/1.42269e-10   0.783276/1.72187e-10   1.01919/1.18991e-10
[Falling Waveform]
V_fixture = 1.8V
V_fixture_min = 1.62V
V_fixture_max = 1.98V
R_fixture = 200Ohm
C_fixture = 0F
|   Time   V(typ)   V(min)   V(max)
0s        1.8V       1.62V      1.98V
1.283ns   1.881V     1.657V     2.116V
1.446ns   1.907V     1.663V     668.8mV
1.703ns   1.89V      1.695V     319.1mV
1.813ns   1.883V     1.711V     303.2mV
2.003ns   621.5mV    1.723V     291.1mV
2.273ns   339.4mV    1.699V     284.9mV
2.618ns   311mV      1.672V     284mV
3.056ns   304mV      377.9mV    283.7mV
6ns       301mV      314.7mV    281.5mV
[Rising Waveform]
V_fixture = 0V
V_fixture_min = 0V
V_fixture_max = 0V
R_fixture = 200Ohm
C_fixture = 0F
|   Time   V(typ)   V(min)   V(max)
0s        1.651uV    22.45uV    806.5nV
1.186ns   -52.01mV   -13.93mV   -116.8mV
1.406ns   -36.63mV   -54.01mV   1.401V
1.64ns    -115.6mV   -51.15mV   1.72V
1.909ns   1.206V     -35.34mV   1.743V
2.185ns   1.507V     -32.33mV   1.745V
2.398ns   1.532V     -56.34mV   1.744V
2.727ns   1.538V     1.005V     1.744V
2.985ns   1.538V     1.251V     1.744V
6ns       1.537V     1.322V     1.742V
[Rising Waveform]
V_fixture = 1.8V
V_fixture_min = 1.62V
V_fixture_max = 1.98V
R_fixture = 200Ohm
C_fixture = 0F
|   Time   V(typ)   V(min)   V(max)
0s        301mV      314.7mV    281.5mV
720.3ps   300.9mV    313mV      320.6mV
922.1ps   312.7mV    312.5mV    723mV
1.189ns   728.6mV    311.9mV    1.041V
1.335ns   935mV      359.2mV    1.756V
1.521ns   1.134V     604.1mV    1.961V
1.645ns   1.152V     779.3mV    1.97V
1.914ns   1.73V      1.057V     1.98V
2.787ns   1.8V       1.58V      1.98V
6ns       1.8V       1.62V      1.98V
[Falling Waveform]
|Gnd
V_fixture = 0V
V_fixture_min = 0V
V_fixture_max = 0V
R_fixture = 200Ohm
C_fixture = 0F
|   Time   V(typ)   V(min)   V(max)
0s        1.539V     1.324V     1.744V
897.4ps   1.535V     1.331V     1.634V
1.284ns   1.188V     1.315V     1.051V
1.419ns   994.1mV    1.275V     277.1mV
1.633ns   742.9mV    1.109V     40.42mV
1.801ns   630.1mV    906.5mV    16.51mV
1.914ns   245.7mV    785.9mV    11.37mV
2.026ns   91.77mV    680.7mV    8.517mV
2.937ns   3.04mV     34.39mV    2.194mV
6ns       1.675uV    22.37uV    756.7nV
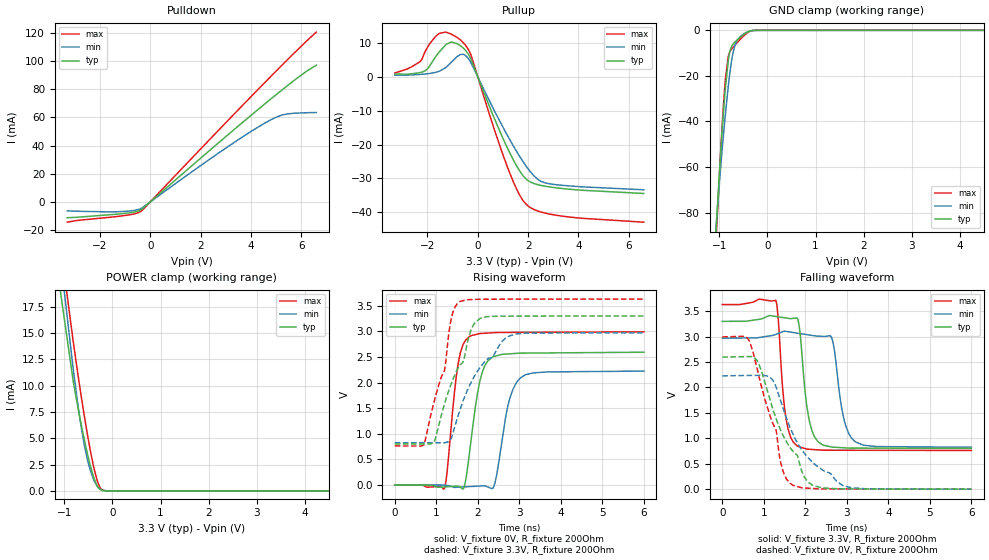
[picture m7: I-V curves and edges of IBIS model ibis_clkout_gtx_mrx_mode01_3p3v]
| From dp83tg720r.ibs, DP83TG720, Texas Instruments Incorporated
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| ibis_clkout_gtx_mrx_mode01_3p3v
[Model]   ibis_clkout_gtx_mrx_mode01_3p3v
Model_type   I/O
Polarity   Non-Inverting
Enable   Active-Low
Vinl = 0.99
Vinh = 2.31
Vmeas = 1.65
Vref = 1.65
Cref = 2pF
Rref = 100000
|   typ   min   max
C_comp   3pF   2.97pF   3.03pF
[Voltage Range]   3.3   2.97   3.63
[Temperature Range]   27   150   -40
[Pullup Reference]   3.3   2.97   3.63
[Pulldown Reference]   0   0   0
[Power Clamp Reference]   3.3   2.97   3.63
[GND Clamp Reference]   0   0   0
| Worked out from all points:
|   slope of the pulldown table from 0 to 0.495 V, typ, clamps not added: 64.1 ohm
|   slope of the pullup table from 0 to 0.495 V, typ, clamps not added: 53.2 ohm
|   GND clamp passes 1 mA (typ) near -0.44 V on its own axis
|   POWER clamp passes 1 mA (typ) near -0.37 V on its own axis
|   falling waveform, V_fixture 3.3V, R_fixture 200Ohm: 20-80 % time 206ps typ, 240ps min, 175ps max; typ from 3.3 V to 0.801 V
|   rising waveform, V_fixture 0V, R_fixture 200Ohm: 20-80 % time 282ps typ, 303ps min, 232ps max; typ from 0 V to 2.59 V
|   rising waveform, V_fixture 3.3V, R_fixture 200Ohm: 20-80 % time 652ps typ, 901ps min, 461ps max; typ from 0.801 V to 3.3 V
|   falling waveform, V_fixture 0V, R_fixture 200Ohm: 20-80 % time 823ps typ, 912ps min, 559ps max; typ from 2.6 V to 0 V
[Pulldown]
|   Voltage   I(typ)   I(min)   I(max)
-3.3V     -11.25mA   -6.349mA   -14.39mA
-2.904V   -10.87mA   -6.6mA     -13.13mA
-1.211V   -8.503mA   -6.909mA   -10.12mA
-617.1mV  -7.122mA   -5.963mA   -8.414mA
-339.9mV  -5.204mA   -4.315mA   -6.257mA
2.927V    45.23mA    37.3mA     54.87mA
4.046V    62.1mA     50.52mA    75.52mA
4.818V    73.49mA    58.58mA    89.59mA
5.056V    76.93mA    60.55mA    93.88mA
5.452V    82.57mA    62.51mA    101mA
6.184V    92.44mA    63.34mA    113.7mA
6.6V      97.15mA    63.52mA    120.6mA
[GND Clamp]
|   Voltage   I(typ)   I(min)   I(max)
-3.3V     -1.014A    -868.6mA   -1.13A
-1.063V   -85.1mA    -84.77mA   -89.5mA
-1.053V   -81.47mA   -81.9mA    -85.32mA
-953.7mV  -47.44mA   -55.17mA   -45.88mA
-894.3mV  -30.21mA   -41.06mA   -26.44mA
-874.5mV  -25.24mA   -36.68mA   -21.3mA
-815.1mV  -13.37mA   -24.58mA   -11.43mA
-745.8mV  -7.082mA   -13.32mA   -8.246mA
-676.5mV  -5.16mA    -6.725mA   -6.511mA
-567.6mV  -3.063mA   -2.829mA   -3.996mA
-409.2mV  -674.4uA   -648.8uA   -987.1uA
6.6V      0A         0A         0A
[Pullup]
|   Voltage   I(typ)   I(min)   I(max)
-3.3V     777.3uA    456.9uA    1.08mA
-2.31V    1.2mA      669.5uA    4.353mA
-2.122V   1.65mA     783.9uA    6.921mA
-1.528V   7.321mA    1.629mA    12.75mA
-1.053V   10.26mA    4.246mA    12.55mA
-815.1mV  9.733mA    5.982mA    11.55mA
-320.1mV  5.932mA    4.769mA    7.263mA
1.125V    -20.17mA   -16.57mA   -25.53mA
1.62V     -27.23mA   -22.94mA   -34.26mA
1.957V    -30.38mA   -26.71mA   -37.83mA
2.788V    -32.42mA   -31.48mA   -40.39mA
6.6V      -34.43mA   -33.33mA   -42.89mA
[POWER Clamp]
|   Voltage   I(typ)   I(min)   I(max)
-3.3V     318.6mA    237.7mA    401.3mA
-1.181V   22.09mA    26.08mA    26.87mA
-815.1mV  10.38mA    11.51mA    14.14mA
-656.7mV  6.467mA    6.258mA    9.187mA
-587.4mV  4.912mA    4.417mA    7.176mA
-528mV    3.676mA    3.125mA    5.551mA
-458.7mV  2.378mA    1.939mA    3.799mA
-369.6mV  1.034mA    857.9uA    1.869mA
-310.2mV  435.8uA    402.8uA    889.1uA
-231mV    77.41uA    103.3uA    169.7uA
-62.7mV   288.2nA    1.832uA    281.8nA
6.6V      0A         0A         0A
[Ramp]
R_load = 200
|   typ   min   max
dV/dt_r   1.55498/2.80393e-10   1.33411/3.00075e-10   1.79397/2.30987e-10
dV/dt_f   1.4992/2.04218e-10   1.28753/2.3963e-10   1.72149/1.74651e-10
[Falling Waveform]
V_fixture = 3.3V
V_fixture_min = 2.97V
V_fixture_max = 3.63V
R_fixture = 200Ohm
C_fixture = 0F
|   Time   V(typ)   V(min)   V(max)
0s        3.3V       2.97V      3.63V
1.29ns    3.396V     3.043V     3.712V
1.526ns   3.367V     3.103V     1.445V
1.804ns   3.367V     3.068V     851.8mV
2.084ns   1.404V     3.033V     785.3mV
2.392ns   882.4mV    3.006V     768.2mV
2.636ns   829.5mV    2.979V     765.8mV
2.932ns   813.4mV    1.376V     765.4mV
3.199ns   807.5mV    934.8mV    765mV
6ns       801.4mV    824.1mV    760.9mV
[Rising Waveform]
V_fixture = 0V
V_fixture_min = 0V
V_fixture_max = 0V
R_fixture = 200Ohm
C_fixture = 0F
|   Time   V(typ)   V(min)   V(max)
0s        2.684uV    34.16uV    1.427uV
1.196ns   -38.34mV   -5.637mV   -71.12mV
1.53ns    -26.39mV   -44.16mV   2.376V
1.673ns   -37.58mV   -37.96mV   2.781V
1.804ns   646mV      -32.32mV   2.9V
2.052ns   2.03V      -21.61mV   2.957V
2.357ns   2.498V     -65.49mV   2.972V
2.719ns   2.558V     1.521V     2.979V
3.018ns   2.574V     2.084V     2.98V
6ns       2.592V     2.224V     2.99V
[Rising Waveform]
V_fixture = 3.3V
V_fixture_min = 2.97V
V_fixture_max = 3.63V
R_fixture = 200Ohm
C_fixture = 0F
|   Time   V(typ)   V(min)   V(max)
0s        801.4mV    824.1mV    760.9mV
705.4ps   800.4mV    823.4mV    782.4mV
947.5ps   828.3mV    823.2mV    1.619V
1.199ns   1.579V     822.9mV    2.241V
1.322ns   1.889V     849.5mV    3.062V
1.415ns   2.086V     1.05V      3.403V
1.567ns   2.34V      1.455V     3.581V
1.927ns   3.162V     2.134V     3.623V
2.771ns   3.297V     2.912V     3.628V
6ns       3.3V       2.97V      3.63V
[Falling Waveform]
|Gnd
V_fixture = 0V
V_fixture_min = 0V
V_fixture_max = 0V
R_fixture = 200Ohm
C_fixture = 0F
|   Time   V(typ)   V(min)   V(max)
0s        2.597V     2.228V     2.994V
656ps     2.608V     2.236V     2.912V
867.2ps   2.487V     2.239V     2.277V
1.201ns   1.624V     2.16V      1.332V
1.3ns     1.381V     2.004V     1.146V
1.452ns   1.082V     1.629V     387.6mV
1.682ns   767.1mV    1.122V     86.92mV
2.068ns   140.6mV    619.2mV    18.8mV
2.915ns   6.118mV    68.37mV    4.497mV
6ns       2.744uV    34.23uV    1.514uV
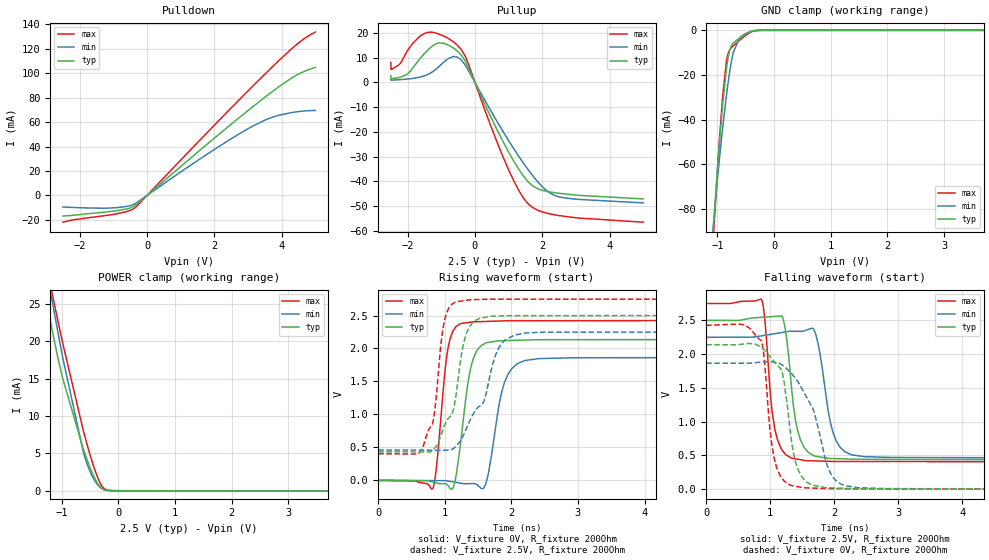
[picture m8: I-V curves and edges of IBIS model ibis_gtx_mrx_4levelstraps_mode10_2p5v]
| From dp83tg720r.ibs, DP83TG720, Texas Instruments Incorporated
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| ibis_gtx_mrx_4levelstraps_mode10_2p5v
[Model]   ibis_gtx_mrx_4levelstraps_mode10_2p5v
Model_type   I/O
Polarity   Non-Inverting
Enable   Active-Low
Vinl = 0.75
Vinh = 1.75
Vmeas = 1.25
Vref = 1.25
Cref = 2pF
Rref = 100000
|   typ   min   max
C_comp   2.5pF   2.47pF   2.53pF
[Voltage Range]   2.5   2.25   2.75
[Temperature Range]   27   150   -40
[Pullup Reference]   2.5   2.25   2.75
[Pulldown Reference]   0   0   0
[Power Clamp Reference]   2.5   2.25   2.75
[GND Clamp Reference]   0   0   0
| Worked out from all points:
|   slope of the pulldown table from 0 to 0.375 V, typ, clamps not added: 42.1 ohm
|   slope of the pullup table from 0 to 0.375 V, typ, clamps not added: 33.6 ohm
|   GND clamp passes 1 mA (typ) near -0.45 V on its own axis
|   POWER clamp passes 1 mA (typ) near -0.36 V on its own axis
|   falling waveform, V_fixture 2.5V, R_fixture 200Ohm: 20-80 % time 160ps typ, 193ps min, 140ps max; typ from 2.5 V to 0.435 V
|   rising waveform, V_fixture 0V, R_fixture 200Ohm: 20-80 % time 170ps typ, 199ps min, 136ps max; typ from 0 V to 2.14 V
|   rising waveform, V_fixture 2.5V, R_fixture 200Ohm: 20-80 % time 284ps typ, 421ps min, 151ps max; typ from 0.435 V to 2.5 V
|   falling waveform, V_fixture 0V, R_fixture 200Ohm: 20-80 % time 197ps typ, 392ps min, 152ps max; typ from 2.14 V to 0 V
[Pulldown]
|   Voltage   I(typ)   I(min)   I(max)
-2.5V     -16.83mA   -9.441mA   -21.92mA
-2.185V   -16.25mA   -9.858mA   -19.94mA
-1.083V   -13.14mA   -10.32mA   -15.85mA
-617.5mV  -11.15mA   -9.099mA   -13.35mA
-362.5mV  -8.408mA   -6.814mA   -10.19mA
1.798V    42.21mA    33.95mA    51.74mA
2.533V    59mA       46.91mA    72.51mA
3.147V    72.69mA    56.82mA    89.62mA
3.74V     85.35mA    64.15mA    105.7mA
4.28V     95.82mA    67.74mA    119.6mA
4.692V    101.8mA    69.17mA    128.8mA
5V        104.8mA    69.59mA    133.7mA
[GND Clamp]
|   Voltage   I(typ)   I(min)   I(max)
-2.5V     -677.3mA   -580.6mA   -757.7mA
-1.097V   -97.67mA   -94.67mA   -103.9mA
-1.03V    -72.76mA   -74.95mA   -75.14mA
-962.5mV  -49.65mA   -56.89mA   -48.25mA
-917.5mV  -35.92mA   -45.91mA   -32.49mA
-835mV    -16.09mA   -27.95mA   -12.9mA
-782.5mV  -8.787mA   -18.33mA   -8.679mA
-722.5mV  -5.711mA   -10.1mA    -6.977mA
-617.5mV  -3.571mA   -3.731mA   -4.617mA
-467.5mV  -1.208mA   -1.06mA    -1.687mA
-272.5mV  -19.58uA   -40.95uA   -21.97uA
5V        0A         0A         0A
[Pullup]
|   Voltage   I(typ)   I(min)   I(max)
-2.5V     2.729mA    1.091mA    8.084mA
-2.478V   1.531mA    935.5uA    5.249mA
-2.268V   1.963mA    1.093mA    7.013mA
-2.02V    3.254mA    1.361mA    12.53mA
-1.472V   12.09mA    2.813mA    19.97mA
-1.135V   15.76mA    5.648mA    19.84mA
-790mV    15.09mA    9.669mA    17.78mA
-287.5mV  8.575mA    6.935mA    10.56mA
852.5mV   -24.33mA   -20.2mA    -30.6mA
1.587V    -40.18mA   -35.34mA   -49.09mA
2.428V    -44.64mA   -45.92mA   -53.6mA
5V        -47.03mA   -48.64mA   -56.43mA
[POWER Clamp]
|   Voltage   I(typ)   I(min)   I(max)
-2.5V     144.7mA    109.6mA    192mA
-1.42V    32.48mA    36.17mA    36.41mA
-1.248V   24.8mA     28.76mA    29.34mA
-1.15V    20.83mA    24.69mA    25.75mA
-985mV    15.15mA    17.98mA    19.89mA
-617.5mV  5.606mA    5.192mA    8.079mA
-550mV    4.155mA    3.595mA    6.186mA
-460mV    2.433mA    1.982mA    3.876mA
-355mV    892.7uA    749.4uA    1.645mA
-257.5mV  177.5uA    191.2uA    370.1uA
-92.5mV   26.93uA    22.57uA    39.12uA
5V        0A         0A         0A
[Ramp]
R_load = 200
|   typ   min   max
dV/dt_r   1.28181/1.6966e-10   1.11812/1.98346e-10   1.45427/1.3468e-10
dV/dt_f   1.23863/1.58336e-10   1.07227/1.90988e-10   1.4069/1.39424e-10
[Falling Waveform]
V_fixture = 2.5V
V_fixture_min = 2.25V
V_fixture_max = 2.75V
R_fixture = 200Ohm
C_fixture = 0F
|   Time   V(typ)   V(min)   V(max)
0s        2.499V     2.249V     2.749V
866.2ps   2.545V     2.271V     2.807V
1.068ns   2.558V     2.302V     919.6mV
1.207ns   2.513V     2.323V     555.3mV
1.321ns   1.642V     2.337V     464.8mV
1.535ns   611mV      2.344V     425.9mV
1.711ns   488.3mV    2.302V     418.4mV
1.978ns   453.6mV    851.6mV    410.6mV
2.263ns   444.3mV    512.4mV    410.1mV
6ns       435mV      462.3mV    404.4mV
[Rising Waveform]
V_fixture = 0V
V_fixture_min = 0V
V_fixture_max = 0V
R_fixture = 200Ohm
C_fixture = 0F
|   Time   V(typ)   V(min)   V(max)
0s        113uV      253.9uV    65.45uV
820.2ps   -24.7mV    -2.731mV   -124mV
1.043ns   -69.93mV   -8.377mV   1.973V
1.148ns   -40.08mV   -26.13mV   2.303V
1.231ns   513mV      -39.97mV   2.374V
1.483ns   1.969V     -64.73mV   2.405V
1.617ns   2.084V     -47.44mV   2.41V
1.897ns   2.119V     1.484V     2.419V
2.184ns   2.127V     1.811V     2.422V
6ns       2.136V     1.864V     2.424V
[Rising Waveform]
V_fixture = 2.5V
V_fixture_min = 2.25V
V_fixture_max = 2.75V
R_fixture = 200Ohm
C_fixture = 0F
|   Time   V(typ)   V(min)   V(max)
0s        435mV      462.3mV    404.4mV
661.8ps   431.6mV    460.1mV    483.1mV
834.8ps   475.2mV    459.5mV    951.8mV
996.9ps   838mV      458.9mV    2.431V
1.164ns   1.26V      516.1mV    2.706V
1.284ns   2.086V     693.5mV    2.724V
1.405ns   2.377V     963.6mV    2.74V
1.807ns   2.492V     2.001V     2.748V
2.052ns   2.498V     2.205V     2.748V
6ns       2.499V     2.249V     2.749V
[Falling Waveform]
|Gnd
V_fixture = 0V
V_fixture_min = 0V
V_fixture_max = 0V
R_fixture = 200Ohm
C_fixture = 0F
|   Time   V(typ)   V(min)   V(max)
0s        2.139V     1.866V     2.426V
861.7ps   2.099V     1.881V     2.201V
1.056ns   1.896V     1.88V      493.4mV
1.192ns   1.72V      1.837V     155.3mV
1.312ns   874.4mV    1.733V     60.71mV
1.501ns   174.4mV    1.48V      24.51mV
1.676ns   56.16mV    1.172V     15.9mV
1.938ns   19.85mV    245.5mV    7.87mV
2.161ns   12.22mV    55.26mV    6.591mV
6ns       111.9uV    253.4uV    64.72uV
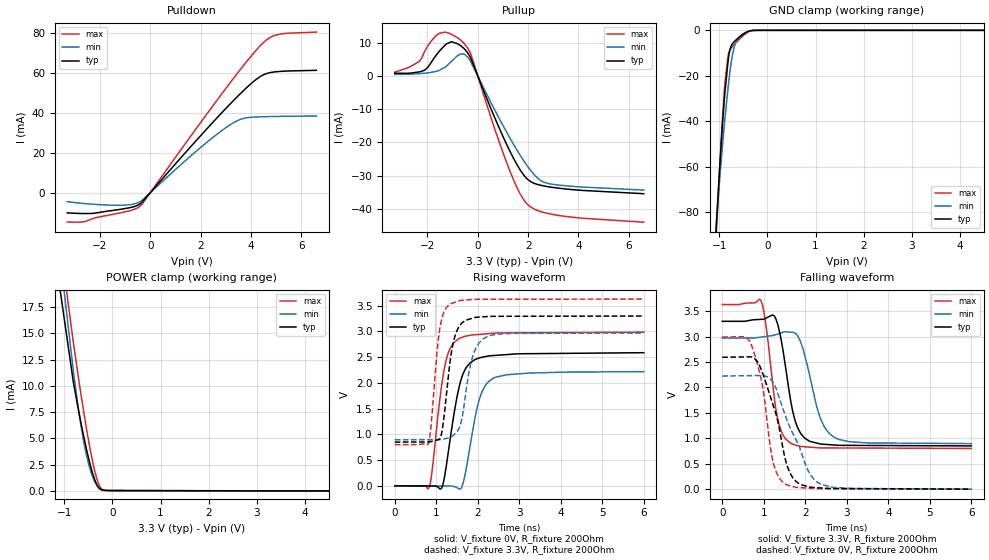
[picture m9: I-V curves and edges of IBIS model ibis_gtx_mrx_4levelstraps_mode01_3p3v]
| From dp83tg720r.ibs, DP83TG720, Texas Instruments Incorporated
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| ibis_gtx_mrx_4levelstraps_mode01_3p3v
[Model]   ibis_gtx_mrx_4levelstraps_mode01_3p3v
Model_type   I/O
Polarity   Non-Inverting
Enable   Active-Low
Vinl = 0.99
Vinh = 2.31
Vmeas = 1.65
Vref = 1.65
Cref = 2pF
Rref = 100000
|   typ   min   max
C_comp   2.5pF   2.46pF   2.54pF
[Voltage Range]   3.3   2.97   3.63
[Temperature Range]   27   150   -40
[Pullup Reference]   3.3   2.97   3.63
[Pulldown Reference]   0   0   0
[Power Clamp Reference]   3.3   2.97   3.63
[GND Clamp Reference]   0   0   0
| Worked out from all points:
|   slope of the pulldown table from 0 to 0.495 V, typ, clamps not added: 69.2 ohm
|   slope of the pullup table from 0 to 0.495 V, typ, clamps not added: 53.2 ohm
|   GND clamp passes 1 mA (typ) near -0.45 V on its own axis
|   POWER clamp passes 1 mA (typ) near -0.36 V on its own axis
|   falling waveform, V_fixture 3.3V, R_fixture 200Ohm: 20-80 % time 312ps typ, 397ps min, 262ps max; typ from 3.3 V to 0.85 V
|   rising waveform, V_fixture 0V, R_fixture 200Ohm: 20-80 % time 336ps typ, 332ps min, 282ps max; typ from 0 V to 2.59 V
|   rising waveform, V_fixture 3.3V, R_fixture 200Ohm: 20-80 % time 231ps typ, 274ps min, 191ps max; typ from 0.85 V to 3.3 V
|   falling waveform, V_fixture 0V, R_fixture 200Ohm: 20-80 % time 484ps typ, 647ps min, 340ps max; typ from 2.59 V to 0 V
[Pulldown]
|   Voltage   I(typ)   I(min)   I(max)
-3.3V     -10.08mA   -4.49mA    -14.66mA
-2.666V   -10.42mA   -5.368mA   -14.59mA
-2.28V    -10.33mA   -5.764mA   -12.91mA
-1.211V   -8.365mA   -6.324mA   -10.16mA
-429mV    -5.796mA   -4.673mA   -6.987mA
1.818V    25.94mA    20.63mA    31.91mA
2.986V    41.87mA    32.34mA    51.81mA
3.62V     49.98mA    36.81mA    62.2mA
4.392V    58.22mA    37.95mA    73.74mA
4.769V    60.04mA    38.06mA    77.63mA
4.966V    60.42mA    38.11mA    78.69mA
6.6V      61.18mA    38.36mA    80.29mA
[GND Clamp]
|   Voltage   I(typ)   I(min)   I(max)
-3.3V     -1.029A    -875.3mA   -1.153A
-1.063V   -85.35mA   -85.15mA   -89.45mA
-1.053V   -81.67mA   -82.25mA   -85.19mA
-953.7mV  -47.17mA   -55.29mA   -45.08mA
-894.3mV  -29.71mA   -41.05mA   -25.54mA
-815.1mV  -12.73mA   -24.4mA    -10.64mA
-765.6mV  -7.51mA    -15.86mA   -8.098mA
-726mV    -5.811mA   -10.61mA   -7.061mA
-676.5mV  -4.664mA   -6.37mA    -5.918mA
-567.6mV  -2.714mA   -2.512mA   -3.568mA
-419.1mV  -648.2uA   -603.7uA   -953.7uA
6.6V      0A         0A         0A
[Pullup]
|   Voltage   I(typ)   I(min)   I(max)
-3.3V     793.6uA    461.8uA    1.11mA
-2.33V    1.194mA    667.6uA    4.324mA
-2.132V   1.671mA    787.6uA    7.026mA
-1.538V   7.318mA    1.632mA    12.73mA
-1.053V   10.25mA    4.299mA    12.52mA
-815.1mV  9.709mA    6.001mA    11.52mA
-537.9mV  8.158mA    6.501mA    9.707mA
-280.5mV  5.304mA    4.257mA    6.565mA
1.125V    -20.21mA   -16.6mA    -25.56mA
1.957V    -30.9mA    -26.91mA   -38.43mA
2.788V    -33.27mA   -32.3mA    -41.31mA
6.6V      -35.39mA   -34.29mA   -43.94mA
[POWER Clamp]
|   Voltage   I(typ)   I(min)   I(max)
-3.3V     318.1mA    237.2mA    400.7mA
-1.181V   22.08mA    26mA       26.9mA
-815.1mV  10.41mA    11.5mA     14.19mA
-656.7mV  6.506mA    6.277mA    9.241mA
-587.4mV  4.953mA    4.443mA    7.232mA
-528mV    3.717mA    3.154mA    5.608mA
-458.7mV  2.419mA    1.969mA    3.857mA
-369.6mV  1.074mA    887uA      1.926mA
-310.2mV  474.3uA    430.6uA    944.6uA
-231mV    113.6uA    129.2uA    222.5uA
-72.6mV   34.18uA    26.12uA    49.79uA
6.6V      0A         0A         0A
[Ramp]
R_load = 200
|   typ   min   max
dV/dt_r   1.55186/3.32634e-10   1.33099/3.2913e-10   1.79129/2.81046e-10
dV/dt_f   1.46906/3.11455e-10   1.24403/3.92567e-10   1.69677/2.61747e-10
[Falling Waveform]
V_fixture = 3.3V
V_fixture_min = 2.97V
V_fixture_max = 3.63V
R_fixture = 200Ohm
C_fixture = 0F
|   Time   V(typ)   V(min)   V(max)
0s        3.299V     2.969V     3.628V
933.5ps   3.337V     2.988V     3.707V
1.048ns   3.359V     3.001V     3.253V
1.294ns   3.343V     3.037V     1.569V
1.452ns   2.784V     3.081V     1.083V
1.638ns   1.794V     3.086V     909.5mV
1.984ns   1.006V     2.643V     833.9mV
2.316ns   898.1mV    1.511V     812.5mV
2.653ns   870.8mV    1.043V     810.3mV
6ns       850.1mV    895.2mV    800.4mV
[Rising Waveform]
V_fixture = 0V
V_fixture_min = 0V
V_fixture_max = 0V
R_fixture = 200Ohm
C_fixture = 0F
|   Time   V(typ)   V(min)   V(max)
0s        216.2uV    481.1uV    128.5uV
824.6ps   -1.968mV   -2.872mV   -41.22mV
896.3ps   -2.158mV   -3.163mV   264.8mV
1.148ns   -6.434mV   -4.187mV   2.052V
1.299ns   701mV      -4.8mV     2.601V
1.53ns    1.841V     -51.33mV   2.852V
1.682ns   2.237V     168.2mV    2.902V
2.045ns   2.485V     1.701V     2.943V
2.387ns   2.532V     2.096V     2.965V
6ns       2.587V     2.219V     2.986V
[Rising Waveform]
V_fixture = 3.3V
V_fixture_min = 2.97V
V_fixture_max = 3.63V
R_fixture = 200Ohm
C_fixture = 0F
|   Time   V(typ)   V(min)   V(max)
0s        850.1mV    895.2mV    800.4mV
814.5ps   852.9mV    898.4mV    821.2mV
1.082ns   912.5mV    899.5mV    3.034V
1.171ns   1.236V     907.6mV    3.343V
1.34ns    2.453V     946.7mV    3.534V
1.466ns   2.949V     1.02V      3.57V
1.61ns    3.159V     1.277V     3.604V
1.891ns   3.261V     2.549V     3.622V
2.234ns   3.289V     2.904V     3.624V
6ns       3.299V     2.969V     3.628V
[Falling Waveform]
|Gnd
V_fixture = 0V
V_fixture_min = 0V
V_fixture_max = 0V
R_fixture = 200Ohm
C_fixture = 0F
|   Time   V(typ)   V(min)   V(max)
0s        2.592V     2.223V     2.99V
530.9ps   2.598V     2.229V     2.997V
690.3ps   2.599V     2.231V     2.858V
961.2ps   2.306V     2.234V     2.069V
1.229ns   1.644V     2.095V     521.9mV
1.518ns   594.4mV    1.451V     102.4mV
1.782ns   149mV      962.8mV    35.71mV
2.131ns   37.45mV    276.4mV    17.87mV
2.398ns   22.56mV    88.95mV    10.72mV
6ns       214.6uV    480.8uV    127.2uV
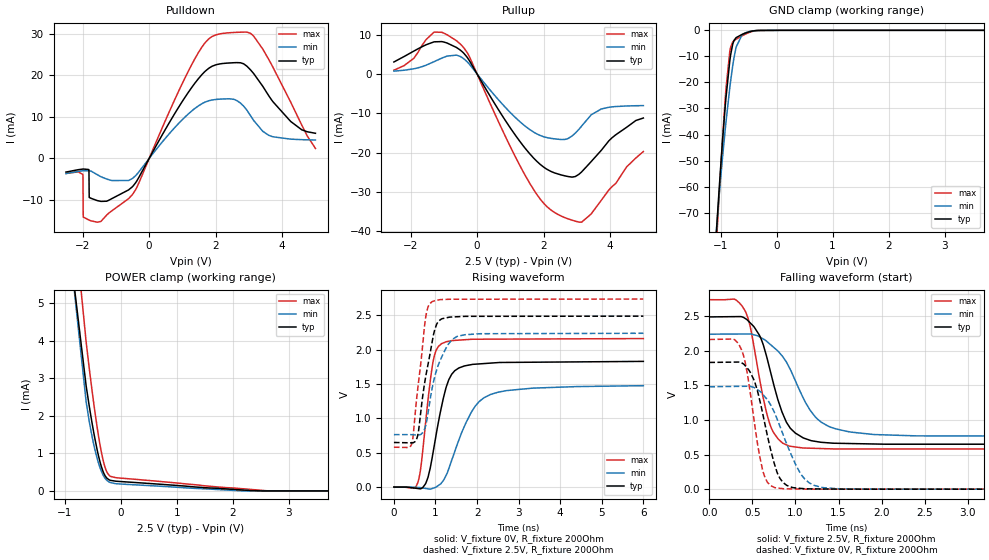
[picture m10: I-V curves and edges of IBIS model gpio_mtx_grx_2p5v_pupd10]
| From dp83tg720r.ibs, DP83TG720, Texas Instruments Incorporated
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| ibis_gtx_mrx_mode10_2p5v
[Model]   gpio_mtx_grx_2p5v_pupd10
Model_type   I/O
Polarity   Non-Inverting
Enable   Active-Low
Vinl = 0.75
Vinh = 1.75
Vmeas = 1.25
Vref = 0
Cref = 2pF
Rref = 100000
|   typ   min   max
C_comp   1.2pF   1.19pF   1.21pF
[Voltage Range]   2.5   2.25   2.75
[Temperature Range]   27   150   -40
[Pullup Reference]   2.5   2.25   2.75
[Pulldown Reference]   0   0   0
[Power Clamp Reference]   2.5   2.25   2.75
[GND Clamp Reference]   0   0   0
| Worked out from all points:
|   slope of the pulldown table from 0 to 0.375 V, typ, clamps not added: 69.3 ohm
|   slope of the pullup table from 0 to 0.375 V, typ, clamps not added: 69.5 ohm
|   GND clamp passes 1 mA (typ) near -0.55 V on its own axis
|   POWER clamp passes 1 mA (typ) near -0.41 V on its own axis
|   falling waveform, V_fixture 2.5V, R_fixture 200Ohm: 20-80 % time 261ps typ, 389ps min, 203ps max; typ from 2.49 V to 0.649 V
|   rising waveform, V_fixture 0V, R_fixture 200Ohm: 20-80 % time 361ps typ, 624ps min, 240ps max; typ from 0 V to 1.83 V
|   rising waveform, V_fixture 2.5V, R_fixture 200Ohm: 20-80 % time 290ps typ, 374ps min, 227ps max; typ from 0.649 V to 2.49 V
|   falling waveform, V_fixture 0V, R_fixture 200Ohm: 20-80 % time 207ps typ, 302ps min, 160ps max; typ from 1.83 V to 0 V
[Pulldown]
|   Voltage   I(typ)   I(min)   I(max)
-2.5V     -3.265mA   -3.621mA   -3.605mA
-1.998V   -2.547mA   -2.969mA   -3.806mA
-1.99V    -2.541mA   -2.964mA   -3.987mA
-1.982V   -2.535mA   -2.958mA   -14.07mA
-1.81V    -2.716mA   -2.945mA   -14.8mA
-1.802V   -9.363mA   -2.952mA   -14.82mA
-1.795V   -9.394mA   -2.961mA   -14.85mA
-617.5mV  -7.551mA   -5.289mA   -9.664mA
1.482V    19.21mA    12.66mA    25.49mA
2.322V    22.93mA    14.34mA    30.18mA
3.147V    20.37mA    9.1mA      29.38mA
5V        6.062mA    4.441mA    2.42mA
[GND Clamp]
|   Voltage   I(typ)   I(min)   I(max)
-2.5V     -617.6mA   -534.2mA   -681mA
-1.097V   -85.14mA   -82.91mA   -90.94mA
-1.038V   -65.04mA   -66.69mA   -67.99mA
-962.5mV  -41.75mA   -48.21mA   -40.95mA
-917.5mV  -29.42mA   -38.23mA   -26.5mA
-835mV    -11.72mA   -22.05mA   -8.12mA
-782.5mV  -5.263mA   -13.52mA   -4.472mA
-722.5mV  -2.803mA   -6.455mA   -3.406mA
-617.5mV  -1.588mA   -1.76mA    -2.13mA
-565mV    -1.134mA   -1.045mA   -1.555mA
-295mV    -44.37uA   -42.73uA   -58.43uA
5V        0A         0A         0A
[Pullup]
|   Voltage   I(typ)   I(min)   I(max)
-2.5V     3.036mA    720.5uA    942.2uA
-1.907V   5.772mA    1.297mA    3.929mA
-1.3V     8.128mA    3.091mA    10.57mA
-617.5mV  6.711mA    4.78mA     8.425mA
-250mV    3.626mA    2.646mA    4.708mA
852.5mV   -11.84mA   -8.504mA   -15.89mA
1.7V      -21.35mA   -14.76mA   -29.36mA
2.217V    -24.74mA   -16.36mA   -34.52mA
2.848V    -26.19mA   -15.81mA   -37.11mA
3.147V    -24.84mA   -13.2mA    -37.61mA
3.732V    -19.41mA   -8.91mA    -32.11mA
5V        -11.19mA   -8.043mA   -19.7mA
[POWER Clamp]
|   Voltage   I(typ)   I(min)   I(max)
-2.5V     97.79mA    60.72mA    150.7mA
-1.09V    8.704mA    8.988mA    11.15mA
-617.5mV  2.796mA    2.372mA    3.967mA
-505mV    1.749mA    1.4mA      2.593mA
-422.5mV  1.106mA    873.9uA    1.712mA
-370mV    774.7uA    620.3uA    1.23mA
-317.5mV  525.8uA    432.3uA    836.9uA
-280mV    406.3uA    338.3uA    626.7uA
-197.5mV  289.2uA    230.9uA    402.1uA
1.272V    112.1uA    72.43uA    172.6uA
2.645V    0A         0A         226nA
5V        0A         0A         0A
[Ramp]
R_load = 200
|   typ   min   max
dV/dt_r   1.09714/3.59889e-10   0.885189/6.2148e-10   1.29627/2.38499e-10
dV/dt_f   1.10299/2.59448e-10   0.884868/3.86759e-10   1.29358/2.02883e-10
[Falling Waveform]
V_fixture = 2.5V
V_fixture_min = 2.25V
V_fixture_max = 2.75V
R_fixture = 200Ohm
C_fixture = 0F
|   Time   V(typ)   V(min)   V(max)
0s        2.487V     2.238V     2.736V
286.6ps   2.491V     2.24V      2.745V
410.8ps   2.469V     2.241V     2.584V
476.8ps   2.398V     2.241V     2.333V
583.5ps   2.217V     2.199V     1.589V
698.5ps   1.75V      2.1V       954.3mV
923.9ps   910.2mV    1.766V     624.1mV
1.24ns    688.7mV    1.032V     589.1mV
1.642ns   659mV      824.7mV    580.9mV
6ns       648.9mV    763.3mV    580mV
[Rising Waveform]
V_fixture = 0V
V_fixture_min = 0V
V_fixture_max = 0V
R_fixture = 200Ohm
C_fixture = 0F
|   Time   V(typ)   V(min)   V(max)
0s        398.9uV    380.4uV    535.1uV
576.6ps   -20.96mV   -6.124mV   67.33mV
662.6ps   -18.98mV   -10.36mV   359.6mV
767.9ps   56.8mV     -20.38mV   969.9mV
933.2ps   473mV      -18.68mV   1.797V
1.148ns   1.178V     63.14mV    2.087V
1.462ns   1.693V     515.4mV    2.135V
1.89ns    1.785V     1.116V     2.151V
2.313ns   1.803V     1.345V     2.152V
6ns       1.829V     1.476V     2.161V
[Rising Waveform]
V_fixture = 2.5V
V_fixture_min = 2.25V
V_fixture_max = 2.75V
R_fixture = 200Ohm
C_fixture = 0F
|   Time   V(typ)   V(min)   V(max)
0s        648.9mV    763.3mV    580mV
432.1ps   643.4mV    762.2mV    637.1mV
579.5ps   772.7mV    756.2mV    1.461V
758.2ps   1.584V     882.2mV    2.448V
822.4ps   1.792V     1.087V     2.624V
912.6ps   2.088V     1.416V     2.695V
1.078ns   2.416V     1.792V     2.724V
1.315ns   2.47V      2.085V     2.733V
1.548ns   2.48V      2.198V     2.734V
6ns       2.487V     2.238V     2.736V
[Falling Waveform]
|Gnd
V_fixture = 0V
V_fixture_min = 0V
V_fixture_max = 0V
R_fixture = 200Ohm
C_fixture = 0F
|   Time   V(typ)   V(min)   V(max)
0s        1.83V      1.479V     2.161V
372ps     1.826V     1.485V     2.017V
438.7ps   1.75V      1.486V     1.681V
514.8ps   1.585V     1.469V     1.035V
616.5ps   1.108V     1.376V     286.1mV
759.6ps   347.6mV    1.094V     22.91mV
857ps     94.72mV    784.1mV    7.161mV
1.055ns   12.34mV    232mV      2.273mV
1.315ns   3.189mV    24.01mV    444.9uV
6ns       400.4uV    383.3uV    536uV
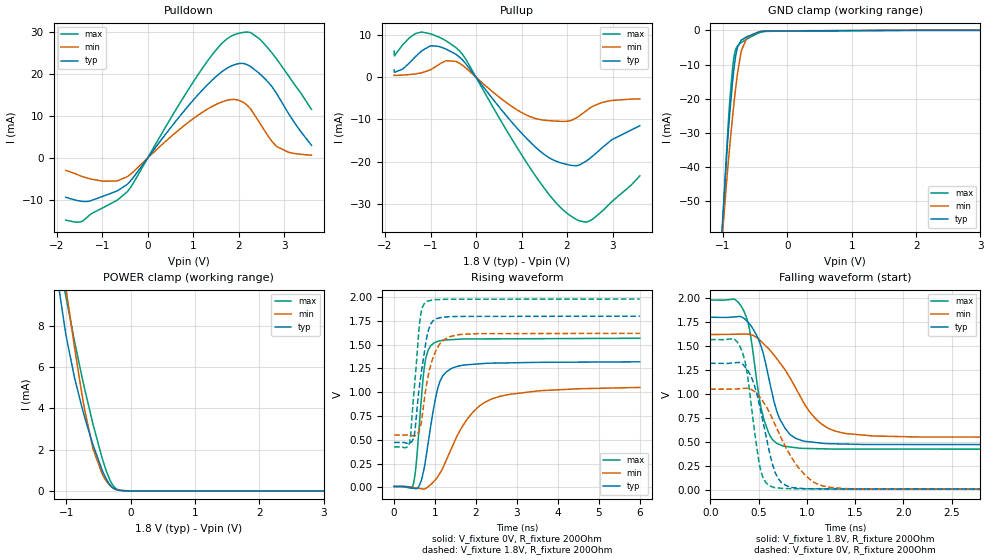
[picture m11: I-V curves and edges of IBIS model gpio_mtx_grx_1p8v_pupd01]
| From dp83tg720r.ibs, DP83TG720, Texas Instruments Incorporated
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[Model]   gpio_mtx_grx_1p8v_pupd01
Model_type   I/O
Polarity   Non-Inverting
Enable   Active-Low
Vinl = 0.54
Vinh = 1.26
Vmeas = 0.9
Vref = 0
Cref = 2pF
Rref = 100000
|   typ   min   max
C_comp   1.19pF   1.18pF   2pF
[Voltage Range]   1.8   1.62   1.98
[Temperature Range]   27   150   -40
[Pullup Reference]   1.8   1.62   1.98
[Pulldown Reference]   0   0   0
[Power Clamp Reference]   1.8   1.62   1.98
[GND Clamp Reference]   0   0   0
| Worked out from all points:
|   slope of the pulldown table from 0 to 0.27 V, typ, clamps not added: 68.8 ohm
|   slope of the pullup table from 0 to 0.27 V, typ, clamps not added: 71.1 ohm
|   GND clamp passes 1 mA (typ) near -0.51 V on its own axis
|   POWER clamp passes 1 mA (typ) near -0.44 V on its own axis
|   falling waveform, V_fixture 1.8V, R_fixture 200Ohm: 20-80 % time 207ps typ, 412ps min, 147ps max; typ from 1.8 V to 0.472 V
|   rising waveform, V_fixture 0V, R_fixture 200Ohm: 20-80 % time 315ps typ, 845ps min, 182ps max; typ from 0.009 V to 1.32 V
|   rising waveform, V_fixture 1.8V, R_fixture 200Ohm: 20-80 % time 240ps typ, 299ps min, 174ps max; typ from 0.472 V to 1.8 V
|   falling waveform, V_fixture 0V, R_fixture 200Ohm: 20-80 % time 176ps typ, 333ps min, 124ps max; typ from 1.32 V to 0.009 V
[Pulldown]
|   Voltage   I(typ)   I(min)   I(max)
-1.8V     -9.373mA   -2.955mA   -14.83mA
-1.503V   -10.24mA   -4.167mA   -15.29mA
-1.287V   -10.3mA    -4.916mA   -13.7mA
-698.4mV  -7.972mA   -5.494mA   -10.23mA
-444.6mV  -6.254mA   -4.425mA   -8.011mA
1.143V    15.5mA     10.46mA    20.44mA
1.597V    20.26mA    13.22mA    26.92mA
1.894V    22.18mA    13.95mA    29.34mA
2.174V    22.29mA    12.67mA    30mA
2.45V     20.2mA     8.58mA     28.46mA
2.839V    15.27mA    2.714mA    23.52mA
3.6V      3.022mA    656uA      11.6mA
[GND Clamp]
|   Voltage   I(typ)   I(min)   I(max)
-1.8V     -346.4mA   -303mA     -380.6mA
-1.012V   -56.87mA   -60.17mA   -58.61mA
-941.4mV  -35.93mA   -43.54mA   -34.16mA
-898.2mV  -24.81mA   -34.31mA   -21.27mA
-849.6mV  -14.45mA   -24.82mA   -10.51mA
-833.4mV  -11.62mA   -21.88mA   -8.151mA
-801mV    -7.157mA   -16.44mA   -5.418mA
-774mV    -4.829mA   -12.43mA   -4.484mA
-720mV    -2.923mA   -6.355mA   -3.607mA
-628.2mV  -1.853mA   -2.087mA   -2.487mA
-304.2mV  -215.9uA   -166.9uA   -299.4uA
3.6V      0A         0A         0A
[Pullup]
|   Voltage   I(typ)   I(min)   I(max)
-1.8V     1.745mA    480.8uA    6.165mA
-1.789V   1.19mA     424.8uA    5.053mA
-1.465V   3.391mA    638.9uA    9.324mA
-1.206V   6.14mA     1.032mA    10.69mA
-828mV    7.328mA    2.927mA    9.562mA
-444.6mV  5.46mA     3.759mA    7.052mA
-223.2mV  3.171mA    2.189mA    4.237mA
1.138V    -14.78mA   -9.105mA   -20.65mA
1.672V    -19.45mA   -10.32mA   -28.65mA
2.25V     -20.85mA   -9.321mA   -33.92mA
2.59V     -18.43mA   -6.746mA   -33.39mA
3.6V      -11.47mA   -5.12mA    -23.35mA
[POWER Clamp]
|   Voltage   I(typ)   I(min)   I(max)
-1.8V     52.85mA    31.95mA    32.56mA
-1.13V    10.13mA    12.61mA    11.55mA
-1.006V   7.541mA    9.807mA    9.387mA
-871.2mV  5.446mA    6.906mA    7.219mA
-720mV    3.615mA    3.996mA    4.997mA
-585mV    2.217mA    2.029mA    3.211mA
-444.6mV  1.012mA    825.1uA    1.592mA
-342mV    379.8uA    327.9uA    665.4uA
-255.6mV  103.8uA    109.9uA    186.5uA
-169.2mV  25.79uA    30.93uA    36.36uA
-1.8mV    170.5nA    164.6nA    213.7nA
3.6V      0A         0A         0A
[Ramp]
R_load = 200
|   typ   min   max
dV/dt_r   0.78656/3.13822e-10   0.625403/8.39906e-10   0.93439/1.80118e-10
dV/dt_f   0.796751/2.06773e-10   0.642365/4.10986e-10   0.932889/1.46699e-10
[Falling Waveform]
V_fixture = 1.8V
V_fixture_min = 1.62V
V_fixture_max = 1.98V
R_fixture = 200Ohm
C_fixture = 0F
|   Time   V(typ)   V(min)   V(max)
0s        1.8V       1.62V      1.98V
245.6ps   1.804V     1.623V     1.99V
345ps     1.792V     1.625V     1.872V
408.8ps   1.728V     1.622V     1.665V
554.4ps   1.4V       1.522V     737.7mV
662.3ps   915.5mV    1.403V     508.5mV
754.3ps   679mV      1.281V     458mV
1.077ns   496.3mV    757.5mV    431mV
1.403ns   478.5mV    588mV      426.2mV
6ns       472mV      549.1mV    425.1mV
[Rising Waveform]
V_fixture = 0V
V_fixture_min = 0V
V_fixture_max = 0V
R_fixture = 200Ohm
C_fixture = 0F
|   Time   V(typ)   V(min)   V(max)
0s        8.977mV    8.24mV     10.35mV
467.6ps   -9.543mV   -1.266mV   31.22mV
543.4ps   -16mV      -6.576mV   266.2mV
742ps     221.4mV    -17.65mV   1.278V
969.4ps   841mV      62.03mV    1.517V
1.129ns   1.125V     154.9mV    1.541V
1.28ns    1.216V     292mV      1.55V
1.784ns   1.289V     717.2mV    1.56V
2.366ns   1.306V     926.5mV    1.561V
6ns       1.32V      1.051V     1.568V
[Rising Waveform]
V_fixture = 1.8V
V_fixture_min = 1.62V
V_fixture_max = 1.98V
R_fixture = 200Ohm
C_fixture = 0F
|   Time   V(typ)   V(min)   V(max)
0s        472mV      549.1mV    425.1mV
381.2ps   464.6mV    546.2mV    476.6mV
492.9ps   550.6mV    540.4mV    1.047V
630.6ps   1.105V     618mV      1.761V
693.1ps   1.291V     775.5mV    1.897V
794.3ps   1.572V     1.088V     1.955V
885.5ps   1.712V     1.272V     1.966V
1.013ns   1.771V     1.432V     1.974V
1.349ns   1.794V     1.583V     1.978V
6ns       1.8V       1.62V      1.98V
[Falling Waveform]
|Gnd
V_fixture = 0V
V_fixture_min = 0V
V_fixture_max = 0V
R_fixture = 200Ohm
C_fixture = 0F
|   Time   V(typ)   V(min)   V(max)
0s        1.32V      1.051V     1.568V
238ps     1.324V     1.051V     1.577V
319.6ps   1.32V      1.056V     1.471V
381.2ps   1.259V     1.06V      1.226V
519.4ps   839.6mV    962.5mV    218.1mV
654.5ps   236.4mV    719.3mV    26.74mV
738ps     76.42mV    533.9mV    17.3mV
910.2ps   19.1mV     237.4mV    12.74mV
1.235ns   10.4mV     27.83mV    10.97mV
6ns       8.977mV    8.24mV     10.35mV
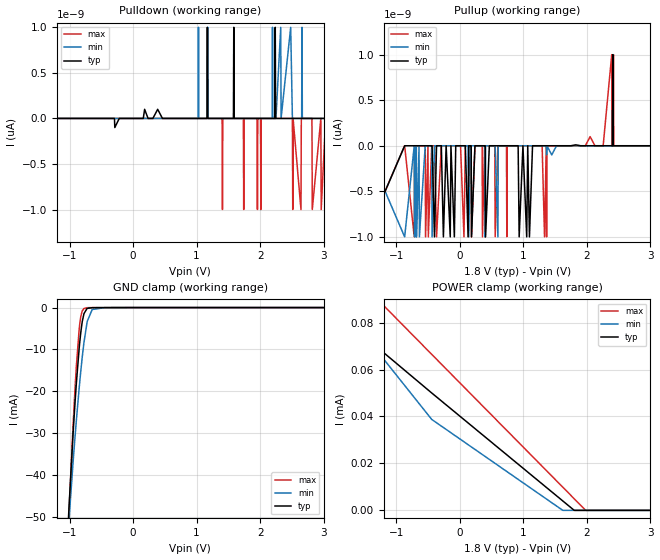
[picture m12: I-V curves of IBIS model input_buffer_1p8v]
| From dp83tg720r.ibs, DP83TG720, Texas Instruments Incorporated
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[Model]   input_buffer_1p8v
Model_type   Input
Vinl = 0.54
Vinh = 1.26
|   typ   min   max
C_comp   0.2pF   0.19pF   0.21pF
[Voltage Range]   1.8   1.62   1.98
[Temperature Range]   27   150   -40
[Power Clamp Reference]   1.8   1.62   1.98
[GND Clamp Reference]   0   0   0
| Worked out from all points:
|   GND clamp passes 1 mA (typ) near -0.76 V on its own axis
|   POWER clamp passes 1 mA (typ) near -1.71 V on its own axis
[Pulldown]
|   Voltage   I(typ)   I(min)   I(max)
-1.8V     0A         0A         0A
1.03V     0A         1fA        0A
1.17V     1fA        0A         0A
1.175V    0A         1fA        0A
1.408V    0A         0A         -1fA
2.196V    0A         1fA        0A
2.239V    1fA        0A         0A
2.326V    0A         1fA        0A
2.515V    0A         0A         -1fA
3.584V    0A         0A         0A
3.589V    0A         0A         -10fA
3.6V      0A         0A         0A
[GND Clamp]
|   Voltage   I(typ)   I(min)   I(max)
-1.8V     -315.1mA   -276.2mA   -344.4mA
-1.033V   -54.85mA   -56.38mA   -56.86mA
-1.006V   -46.88mA   -50.09mA   -47.71mA
-941.4mV  -29.22mA   -36.18mA   -27.08mA
-892.8mV  -17.95mA   -26.84mA   -13.87mA
-838.8mV  -8.066mA   -17.55mA   -3.748mA
-801mV    -3.376mA   -11.86mA   -812.1uA
-774mV    -1.451mA   -8.346mA   -228.2uA
-720mV    -188.8uA   -3.208mA   -33.36uA
-644.4mV  -21.52uA   -467uA     -18.09uA
-444.6mV  -9.905uA   -9.406uA   -12.18uA
3.6V      0A         0A         0A
[Pullup]
|   Voltage   I(typ)   I(min)   I(max)
-1.8V     0A         0A         800fA
-1.795V   0A         0A         0A
-1.487V   -1fA       0A         -1fA
-871.2mV  0A         -1fA       0A
-720mV    0A         0A         -1fA
-714.6mV  0A         -1fA       0A
-541.8mV  0A         0A         -1fA
-439.2mV  0A         -1fA       0A
-401.4mV  -1fA       0A         0A
1.364V    0A         0A         -1fA
2.39V     0A         0A         1fA
3.6V      0A         0A         0A
[POWER Clamp]
|   Voltage   I(typ)   I(min)   I(max)
-1.8V     2.324mA    3.081mA    2.218mA
-1.46V    86.76uA    222.6uA    96.45uA
-1.395V   75.3uA     128.1uA    93.04uA
-1.379V   73.85uA    114uA      92.44uA
-1.265V   68.66uA    66.61uA    89.02uA
-444.6mV  50.02uA    38.75uA    66.48uA
1.618V    4.045uA    26.85nA    9.914uA
1.796V    73.51nA    0A         5.028uA
1.985V    0A         0A         0A
3.6V      0A         0A         0A
